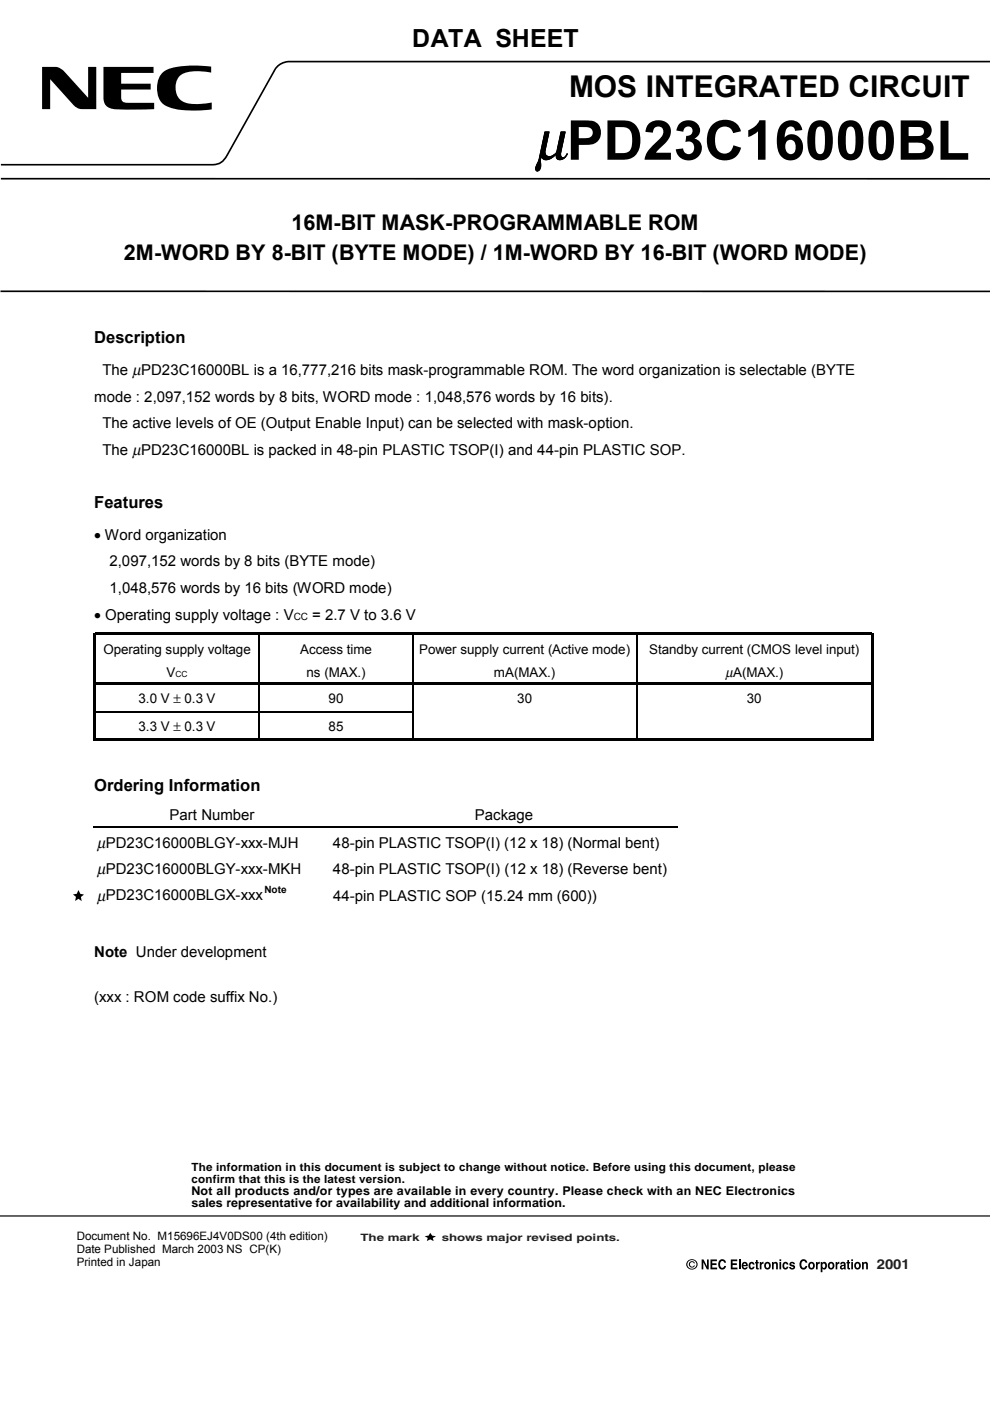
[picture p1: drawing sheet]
<svg xmlns="http://www.w3.org/2000/svg" width="210mm" height="297mm" viewBox="0 0 210 297" stroke-linecap="round" stroke-linejoin="round" font-family="sans-serif">
<defs><g id="words">
<text font-size="11.9" x="113.6" y="33.7">µPD23C16000BL</text>
<text font-size="6.3" x="120.6" y="20.6">MOS INTEGRATED CIRCUIT</text>
<text font-size="5.3" x="87.4" y="9.9">DATA SHEET</text>
<g font-size="4.6">
<text x="61.8" y="48.9">16M-BIT MASK-PROGRAMMABLE ROM</text>
<text x="26.3" y="55.2">2M-WORD BY 8-BIT (BYTE MODE) / 1M-WORD BY 16-BIT (WORD MODE)</text>
</g>
<g font-size="3.5">
<text x="20" y="72.7">Description</text>
<text x="20" y="107.6">Features</text>
<text x="20" y="167.7">Ordering Information</text>
</g>
<g font-size="3.2">
<text x="21.8" y="79.5">The µPD23C16000BL is a 16,777,216 bits mask-programmable ROM. The word organization is selectable (BYTE</text>
<text x="20" y="85.2">mode : 2,097,152 words by 8 bits, WORD mode : 1,048,576 words by 16 bits).</text>
<text x="21.8" y="90.8">The active levels of OE (Output Enable Input) can be selected with mask-option.</text>
<text x="21.8" y="96.4">The µPD23C16000BL is packed in 48-pin PLASTIC TSOP(I) and 44-pin PLASTIC SOP.</text>
<text x="20" y="114.4">• Word organization</text>
<text x="23.2" y="120.1">2,097,152 words by 8 bits (BYTE mode)</text>
<text x="23.2" y="125.7">1,048,576 words by 16 bits (WORD mode)</text>
<text x="20" y="131.4">• Operating supply voltage : V</text>
<text x="66.2" y="131.4">= 2.7 V to 3.6 V</text>
<text x="35.9" y="173.8">Part Number</text>
<text x="100.7" y="173.8">Package</text>
<text x="20.6" y="179.7">µPD23C16000BLGY-xxx-MJH</text>
<text x="70.6" y="179.7">48-pin PLASTIC TSOP(I) (12 x 18) (Normal bent)</text>
<text x="20.6" y="185.3">µPD23C16000BLGY-xxx-MKH</text>
<text x="70.6" y="185.3">48-pin PLASTIC TSOP(I) (12 x 18) (Reverse bent)</text>
<text x="20.6" y="190.9">µPD23C16000BLGX-xxx</text>
<text x="70.6" y="191">44-pin PLASTIC SOP (15.24 mm (600))</text>
<text x="20" y="202.9">Note Under development</text>
<text x="20" y="212.5">(xxx : ROM code suffix No.)</text>
</g>
<text font-size="2.9" x="153.8" y="143.6">µA(MAX.)</text>
<text font-size="2.9" fill="#231f20" x="185.9" y="269.1">2001</text>
<g font-size="2.8">
<text x="21.9" y="138.7">Operating supply voltage</text>
<text x="35.3" y="143.6">V</text>
<text x="63.6" y="138.7">Access time</text>
<text x="65" y="143.6">ns (MAX.)</text>
<text x="88.9" y="138.7">Power supply current (Active mode)</text>
<text x="104.7" y="143.6">mA(MAX.)</text>
<text x="137.6" y="138.7">Standby current (CMOS level input)</text>
<text x="29.4" y="149.1">3.0 V ± 0.3 V</text>
<text x="69.7" y="149.1">90</text>
<text x="109.7" y="149.1">30</text>
<text x="158.4" y="149.1">30</text>
<text x="29.4" y="155">3.3 V ± 0.3 V</text>
<text x="69.7" y="155">85</text>
</g>
<g font-size="2.6">
<text x="40.6" y="253.4">Not all products and/or types are available in every country. Please check with an NEC Electronics</text>
<text x="40.6" y="256">sales representative for availability and additional information.</text>
</g>
<g font-size="2.5">
<text x="16.3" y="262.8">Document No. M15696EJ4V0DS00 (4th edition)</text>
<text x="16.3" y="265.6">Date Published March 2003 NS CP(K)</text>
<text x="16.3" y="268.5">Printed in Japan</text>
</g>
<g font-size="2.4">
<text x="40.6" y="248.3">The information in this document is subject to change without notice. Before using this document, please</text>
<text x="40.6" y="250.8">confirm that this is the latest version.</text>
</g>
<g font-size="2.2" fill="#231f20">
<text x="76.4" y="263">The mark</text>
<text x="93.6" y="263">shows major revised points.</text>
</g>
<g font-size="2.1">
<text x="62.3" y="131.4">CC</text>
<text x="56" y="189.3">Note</text>
</g>
<text font-size="1.8" x="37.2" y="143.6">CC</text>
</g></defs>
<path d="M210 13.1h-148.9a3.5 3.5 0 0 0-3 1.9l-10 17.9a3.2 3.2 0 0 1-3 2h-44.9M.2 37.9h209.8M.1 61.8h209.8" fill="none" stroke="#000" stroke-width=".35"/>
<g fill="#000">
<path d="M8.9 14.2h2.9l1.2 .5 5.7 6v-6.5h1.7v8.9h-3l-1.2-.3-5.6-6v6.3h-1.7zM21.9 14.2h10.7v1.3h-6.9v2.2h6.2v1.3h-6.2v1.6a1.12 1.12 0 0 0 1.5 1.2h5.5v1.3l-7.1 .1a3.9 3.9 0 0 1-3.3-1l-.4-1.4zM34.5 15.4a10.2 10.2 0 0 1 6.2-1.5l4.1 .2v1.3a9.3 9.3 0 0 0-6.4 .5 3.7 3.7 0 0 0 .2 5.5 10.3 10.3 0 0 0 6.3 .3v1.5a21.7 21.7 0 0 1-9.2-.5 4.3 4.3 0 0 1-2.3-5.2 3.8 3.8 0 0 1 1.1-2.1zM19.7 134.2h.5v.5h-.5zM20.2 134.2h34.7v.5h-34.7zM54.9 134.7h.2zM54.9 134.2h32.5v.5h-32.5zM87.4 134.7h.2zM87.4 134.2h47.5v.5h-47.5zM134.9 134.7h.2zM134.9 134.2h49.8v.5h-49.8zM184.7 134.2h.6v.5h-.6z"/>
<path d="M19.7 134.7h.5v9.9h-.5zM19.7 144.6h.5v.5h-.5zM19.7 145.1h.5v5.6h-.5zM19.7 151h.5v6.1h-.5zM20.2 144.6h34.7v.5h-34.7zM20.2 156.6h34.7v.5h-34.7zM54.9 145.1h.2zM54.9 144.6h32.5v.5h-32.5zM54.9 156.6h32.5v.5h-32.5zM87.4 145.1h.2zM87.4 144.6h47.5v.5h-47.5zM87.4 156.6h47.5v.5h-47.5z"/>
<path d="M134.9 145.1h.2zM134.9 144.6h49.8v.5h-49.8zM134.9 150.7h.2v.3h-.2zM134.9 156.6h49.8v.5h-49.8zM184.7 134.7h.6v9.9h-.6zM184.7 144.6h.6v.5h-.6zM184.7 145.1h.6v5.6h-.6zM184.7 150.7h.6v.3h-.6zM184.7 151h.6v6.1h-.6zM15.5 189.6l.8-.1 .3-.8 .4 .8 .8 .2-.6 .5 .1 .9-.7-.5-.7 .4 .2-.9zM90 262.1l.9-.1 .3-.6 .4 .6 .8 .1-.6 .4 .1 .6-.7-.3-.7 .3 .2-.6zM148.8 267h.4l.7 1.5v-1.5h.4v2.1h-.4l-.8-1.5v1.5h-.3z"/>
<path d="M150.6 267h1.4v.4h-1v.4h.9v.4h-.9v.6h1v.3h-1.4zM152.5 267.3a.79 .79 0 0 1 .9-.3 .79 .79 0 0 1 .5 .7h-.4l-.1-.3a.43 .43 0 0 0-.7 .3v.4a.48 .48 0 0 0 .1 .6 .48 .48 0 0 0 .7-.1v-.2h.4a.85 .85 0 0 1-1 .8 .85 .85 0 0 1-.6-1.1zM154.9 267h1.4v.4h-1v.4h.9v.4h-.9v.6h1.1v.3h-1.5zM158.9 267.8a.62 .62 0 0 1 .7-.2 .62 .62 0 0 1 .4 .5h-.4v-.1a.41 .41 0 0 0-.5 .3 .41 .41 0 0 0 .4 .5l.1-.2h.4a.64 .64 0 0 1-.7 .6 .64 .64 0 0 1-.6-.8zM160.3 267.2h.3v.4h.3v.3h-.3v.8l.3 .1v.3l-.6-.1v-1.1h-.2v-.3h.2zM161.1 267.6h.3v.2l.2-.2 .3-.1v.5l-.4 .1v1h-.4zM163.7 267.6h.3v.2l.1-.1a.47 .47 0 0 1 .8 .1v1.3h-.3l-.1-1-.2-.2-.2 .1-.1 1.1h-.3zM166 267.8a.62 .62 0 0 1 .7-.2 .62 .62 0 0 1 .5 .5h-.4l-.1-.1a.41 .41 0 0 0-.4 .3 .41 .41 0 0 0 .4 .5l.1-.2h.4a.64 .64 0 0 1-.8 .6 .64 .64 0 0 1-.5-.8zM167.6 267.6a.62 .62 0 0 1 .9 .4h-.3l-.3-.2-.2 .2 .2 .1a.58 .58 0 0 1 .5 .2 .58 .58 0 0 1 .1 .6l-.5 .3a.57 .57 0 0 1-.7-.6h.4l.3 .3 .2-.2-.1-.1a.57 .57 0 0 1-.7-.8zM169.8 267.3a.79 .79 0 0 1 .8-.3 .79 .79 0 0 1 .6 .7h-.4l-.2-.3a.43 .43 0 0 0-.6 .3l-.1 .4a.48 .48 0 0 0 .2 .6 .48 .48 0 0 0 .6-.1l.1-.2h.4a.85 .85 0 0 1-1 .8 .85 .85 0 0 1-.7-1.1zM173 267.6h.4v.2l.2-.2 .2-.1v.5l-.4 .1v1h-.4zM177.2 267.6h.3v.2l.2-.2 .3-.1v.5l-.4 .1-.1 1h-.3z"/>
<path d="M179.7 267.2h.3v.4h.2v.3h-.2v.8l.2 .1v.3l-.5-.1v-1.1h-.2v-.3h.2zM182.8 267.6h.3v.2l.1-.1a.47 .47 0 0 1 .7 .1l.1 1.3h-.3l-.1-1-.2-.2-.2 .1-.1 1.1h-.3z"/>
<path d="M145.5 268.1a1.16 1.16 0 0 1 2.3 0 1.16 1.16 0 0 1-2.3 0zM145.8 268.1a.95 .95 0 0 0 1.9 0 .95 .95 0 0 0-1.9 0zM146.2 267.6a.67 .67 0 0 1 1.1 .3h-.2a.44 .44 0 0 0-.7-.2 .44 .44 0 0 0 0 .7 .44 .44 0 0 0 .7-.1h.2a.67 .67 0 0 1-1 .3 .67 .67 0 0 1-.1-1z"/>
<path d="M157.6 267.6h.5a.84 .84 0 0 1 .5 .9h-1l.1 .3h.2l.6-.1a.64 .64 0 0 1-.6 .5 .64 .64 0 0 1-.6-.5 1.02 1.02 0 0 1 .3-1.1zM157.8 267.9l-.2 .3h.6l-.2-.3z"/>
<path d="M162.2 267.7a.76 .76 0 0 1 1.2 .6 .76 .76 0 0 1-1.2 .7 1.01 1.01 0 0 1 0-1.3zM162.5 268l-.1 .1a.42 .42 0 0 0 .1 .5 .42 .42 0 0 0 .4 .1l.1-.1a.42 .42 0 0 0 0-.5 .42 .42 0 0 0-.5-.1z"/>
<path d="M165.3 267.6h.3v1.5h-.3zM165.3 267h.3v.4h-.3z"/>
<path d="M171.6 267.7a.76 .76 0 0 1 1.2 .6 .76 .76 0 0 1-1.2 .7 1.01 1.01 0 0 1 0-1.3zM171.8 268l-.1 .1a.42 .42 0 0 0 .1 .5 .42 .42 0 0 0 .5 .1l.1-.1a.42 .42 0 0 0-.1-.5 .42 .42 0 0 0-.5-.1z"/>
<path d="M174 267.6h.4v.2v-.1a.5 .5 0 0 1 .6-.1 .5 .5 0 0 1 .3 .4 .7 .7 0 0 1 0 .8 .7 .7 0 0 1-.9 .2v-.1v.8h-.4zM174.5 268l-.1 .1a.48 .48 0 0 0 .3 .7 .45 .45 0 0 0 .3-.5 .45 .45 0 0 0-.5-.3z"/>
<path d="M175.7 267.7a.76 .76 0 0 1 1.2 .6 .76 .76 0 0 1-1.2 .7 1.01 1.01 0 0 1 0-1.3zM176 268l-.1 .1a.42 .42 0 0 0 .1 .5 .42 .42 0 0 0 .4 .1l.1-.1a.42 .42 0 0 0 0-.5 .42 .42 0 0 0-.5-.1z"/>
<path d="M178.3 267.6l.2-.1a.56 .56 0 0 1 .8 .5l.1 1.1h-.4l-.1-.2a.48 .48 0 0 1-.8 .1 .48 .48 0 0 1 .4-.8l.4-.2-.2-.1-.2 .2h-.4zM178.5 268.5v.3h.3l.1-.4z"/>
<path d="M180.5 267.6h.3v1.5h-.3zM180.5 267h.3v.4h-.3z"/>
<path d="M181.3 267.7a.76 .76 0 0 1 1.2 .6 .76 .76 0 0 1-1.2 .7 1.01 1.01 0 0 1 0-1.3zM181.6 268l-.1 .1a.42 .42 0 0 0 .1 .5 .42 .42 0 0 0 .4 .1l.1-.1a.42 .42 0 0 0 0-.5 .42 .42 0 0 0-.5-.1z"/>
</g>
<path d="M55 134.7v9.9M87.5 134.7v9.9M135 134.7v9.9M19.7 150.9h67.9M55 145.1v5.6M55 151v5.6M87.5 145.1v5.6M87.5 151v5.6M135 145.1v5.6M135 151v5.6M19.9 175.3h123.8M0 257.8h209.9" fill="none" stroke="#000" stroke-width=".25"/>
<path d="M156.8 267v2.1" fill="none" stroke="#000" stroke-width=".36"/>
<use href="#words"/>
</svg>
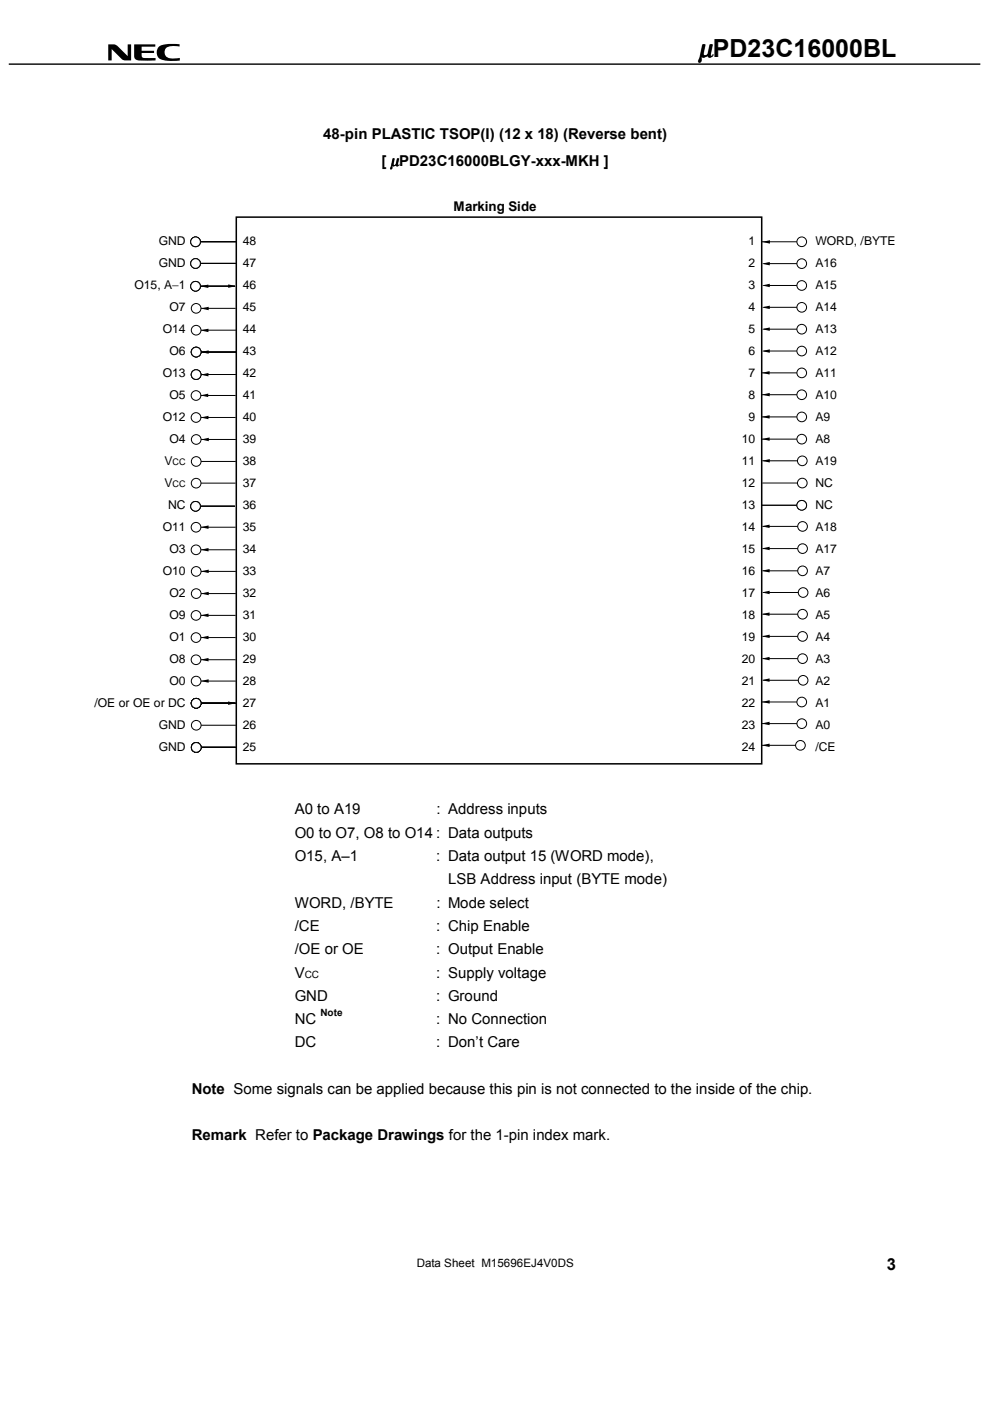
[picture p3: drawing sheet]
<svg xmlns="http://www.w3.org/2000/svg" width="210mm" height="297mm" viewBox="0 0 210 297" stroke-linecap="round" stroke-linejoin="round" font-family="sans-serif">
<defs><g id="words">
<text font-size="5.4" x="148.2" y="12">µPD23C16000BL</text>
<text font-size="3.5" x="188" y="269.2">3</text>
<g font-size="3.2">
<text x="68.5" y="29.5">48-pin PLASTIC TSOP(I) (12 x 18) (Reverse bent)</text>
<text x="80.9" y="35.1">[ µPD23C16000BLGY-xxx-MKH ]</text>
<text x="62.5" y="172.7">A0 to A19</text>
<text x="92.5" y="172.7">: Address inputs</text>
<text x="62.5" y="177.6">O0 to O7, O8 to O14 : Data outputs</text>
<text x="62.5" y="182.6">O15, A–1</text>
<text x="92.5" y="182.6">: Data output 15 (WORD mode),</text>
<text x="95" y="187.5">LSB Address input (BYTE mode)</text>
<text x="62.5" y="192.4">WORD, /BYTE</text>
<text x="62.5" y="197.4">/CE</text>
<text x="92.5" y="197.4">: Chip Enable</text>
<text x="92.5" y="192.4">: Mode select</text>
<text x="62.5" y="202.3">/OE or OE</text>
<text x="92.5" y="202.3">: Output Enable</text>
<text x="62.5" y="207.3">V</text>
<text x="92.5" y="207.3">: Supply voltage</text>
<text x="62.5" y="212.2">GND</text>
<text x="92.5" y="212.2">: Ground</text>
<text x="62.5" y="217">NC</text>
<text x="92.5" y="217">: No Connection</text>
<text x="62.5" y="222.1">DC</text>
<text x="92.5" y="222.1">: Don’t Care</text>
<text x="40.6" y="231.9">Note Some signals can be applied because this pin is not connected to the inside of the chip.</text>
<text x="40.6" y="241.8">Remark Refer to Package Drawings for the 1-pin index mark.</text>
</g>
<text font-size="2.8" x="96.2" y="44.7">Marking Side</text>
<g font-size="2.6">
<text x="33.6" y="51.9">GND</text>
<text x="51.5" y="51.9">48</text>
<text x="158.7" y="51.9">1</text>
<text x="172.9" y="51.9">WORD, /BYTE</text>
<text x="33.6" y="56.6">GND</text>
<text x="51.5" y="56.6">47</text>
<text x="158.7" y="56.6">2</text>
<text x="172.9" y="56.6">A16</text>
<text x="28.5" y="61.2">O15, A−1</text>
<text x="35.9" y="65.9">O7</text>
<text x="51.5" y="61.2">46</text>
<text x="51.5" y="65.9">45</text>
<text x="158.7" y="61.2">3</text>
<text x="158.7" y="65.9">4</text>
<text x="172.9" y="61.2">A15</text>
<text x="172.9" y="65.9">A14</text>
<text x="34.5" y="70.6">O14</text>
<text x="51.5" y="70.6">44</text>
<text x="158.7" y="70.6">5</text>
<text x="172.9" y="70.6">A13</text>
<text x="35.9" y="75.2">O6</text>
<text x="51.5" y="75.2">43</text>
<text x="158.7" y="75.2">6</text>
<text x="172.9" y="75.2">A12</text>
<text x="34.5" y="79.9">O13</text>
<text x="51.5" y="79.9">42</text>
<text x="158.7" y="79.9">7</text>
<text x="172.9" y="79.9">A11</text>
<text x="34.5" y="89.2">O12</text>
<text x="35.9" y="84.5">O5</text>
<text x="51.5" y="84.5">41</text>
<text x="51.5" y="89.2">40</text>
<text x="158.7" y="84.5">8</text>
<text x="158.7" y="89.2">9</text>
<text x="172.9" y="84.5">A10</text>
<text x="172.9" y="89.2">A9</text>
<text x="35.9" y="93.9">O4</text>
<text x="51.5" y="93.9">39</text>
<text x="157.3" y="93.9">10</text>
<text x="172.9" y="93.9">A8</text>
<text x="34.9" y="98.5">V</text>
<text x="51.5" y="98.5">38</text>
<text x="157.3" y="98.5">11</text>
<text x="172.9" y="98.5">A19</text>
<text x="34.9" y="103.2">V</text>
<text x="35.7" y="107.9">NC</text>
<text x="51.5" y="103.2">37</text>
<text x="51.5" y="107.9">36</text>
<text x="157.3" y="103.2">12</text>
<text x="157.3" y="107.9">13</text>
<text x="172.9" y="103.2">NC</text>
<text x="172.9" y="107.9">NC</text>
<text x="34.5" y="112.5">O11</text>
<text x="51.5" y="112.5">35</text>
<text x="157.3" y="112.5">14</text>
<text x="172.9" y="112.5">A18</text>
<text x="35.9" y="117.2">O3</text>
<text x="51.5" y="117.2">34</text>
<text x="157.3" y="117.2">15</text>
<text x="172.9" y="117.2">A17</text>
<text x="34.5" y="121.8">O10</text>
<text x="51.5" y="121.8">33</text>
<text x="157.3" y="121.8">16</text>
<text x="172.9" y="121.8">A7</text>
<text x="35.9" y="126.5">O2</text>
<text x="35.9" y="131.2">O9</text>
<text x="51.5" y="126.5">32</text>
<text x="51.5" y="131.2">31</text>
<text x="157.3" y="126.5">17</text>
<text x="157.3" y="131.2">18</text>
<text x="172.9" y="126.5">A6</text>
<text x="172.9" y="131.2">A5</text>
<text x="35.9" y="135.8">O1</text>
<text x="51.5" y="135.8">30</text>
<text x="157.3" y="135.8">19</text>
<text x="172.9" y="135.8">A4</text>
<text x="35.9" y="140.5">O8</text>
<text x="51.5" y="140.5">29</text>
<text x="157.3" y="140.5">20</text>
<text x="172.9" y="140.5">A3</text>
<text x="20" y="149.8">/OE or OE or DC</text>
<text x="35.9" y="145.2">O0</text>
<text x="51.5" y="145.2">28</text>
<text x="51.5" y="149.8">27</text>
<text x="157.3" y="145.2">21</text>
<text x="157.3" y="149.8">22</text>
<text x="172.9" y="145.2">A2</text>
<text x="172.9" y="149.8">A1</text>
<text x="33.6" y="154.5">GND</text>
<text x="51.5" y="154.5">26</text>
<text x="157.3" y="154.5">23</text>
<text x="172.9" y="154.5">A0</text>
<text x="33.6" y="159.1">GND</text>
<text x="51.5" y="159.1">25</text>
<text x="157.3" y="159.1">24</text>
<text x="172.9" y="159.1">/CE</text>
</g>
<text font-size="2.5" x="88.3" y="268.7">Data Sheet M15696EJ4V0DS</text>
<g font-size="2.1">
<text x="64.6" y="207.3">CC</text>
<text x="67.9" y="215.4">Note</text>
</g>
<g font-size="1.9">
<text x="36.6" y="98.5">CC</text>
<text x="36.6" y="103.2">CC</text>
</g>
</g></defs>
<path d="M1.9 13.6h206" fill="none" stroke="#000" stroke-width=".31"/>
<path d="M23 9.4h1.2l.5 .2 2.4 2.3v-2.5h.7v3.4l-1.7-.1-2.4-2.3v2.4h-.7zM28.4 9.4h4.5v.5h-2.9v.9h2.7v.4h-2.7v.6a.63 .63 0 0 0 .9 .5h2.1v.5h-2.8a1.48 1.48 0 0 1-1.7-.6zM33.6 10a5.9 5.9 0 0 1 4.5-.6v.5l-1.2-.1a1.52 1.52 0 0 0-2 1.3 1.34 1.34 0 0 0 1.6 1.3l1.6-.1v.5a7.1 7.1 0 0 1-4.4-.5l-.4-.5-.1-.7z" fill="#000"/>
<path d="M50.1 46h111.4v115.9h-111.4z" fill="none" stroke="#000" stroke-width=".32"/>
<path d="M161.5 107.1h8.5" fill="none" stroke="#000" stroke-width=".21"/>
<circle cx="170" cy="107.1" r="1.02" fill="#fff" stroke="#000" stroke-width=".21"/>
<path d="M161.5 79.1h8.5" fill="none" stroke="#000" stroke-width=".21"/>
<circle cx="170" cy="79.1" r="1.02" fill="#fff" stroke="#000" stroke-width=".21"/>
<path d="M161.5 51.3h8.5" fill="none" stroke="#000" stroke-width=".21"/>
<circle cx="170" cy="51.3" r="1.02" fill="#fff" stroke="#000" stroke-width=".21"/>
<path d="M161.9 55.9h8.1" fill="none" stroke="#000" stroke-width=".21"/>
<circle cx="170" cy="55.9" r="1.02" fill="#fff" stroke="#000" stroke-width=".21"/>
<path d="M161.6 55.9l1.6-.4v.8z" fill="#000"/>
<path d="M161.9 60.5h8.1" fill="none" stroke="#000" stroke-width=".21"/>
<circle cx="170" cy="60.5" r="1.02" fill="#fff" stroke="#000" stroke-width=".21"/>
<path d="M161.6 60.5l1.6-.3v.7z" fill="#000"/>
<path d="M161.9 65.2h8.1" fill="none" stroke="#000" stroke-width=".21"/>
<circle cx="170" cy="65.2" r="1.02" fill="#fff" stroke="#000" stroke-width=".21"/>
<path d="M161.6 65.2l1.6-.4v.7z" fill="#000"/>
<path d="M161.9 69.8h8.1" fill="none" stroke="#000" stroke-width=".21"/>
<circle cx="170" cy="69.8" r="1.02" fill="#fff" stroke="#000" stroke-width=".21"/>
<path d="M161.6 69.8l1.6-.4v.8z" fill="#000"/>
<path d="M161.9 74.4h8.1" fill="none" stroke="#000" stroke-width=".21"/>
<circle cx="170" cy="74.4" r="1.02" fill="#fff" stroke="#000" stroke-width=".21"/>
<path d="M161.6 74.4l1.6-.3v.7z" fill="#000"/>
<path d="M161.5 83.7h8.5" fill="none" stroke="#000" stroke-width=".21"/>
<circle cx="170" cy="83.7" r="1.02" fill="#fff" stroke="#000" stroke-width=".21"/>
<path d="M161.5 88.4h8.5" fill="none" stroke="#000" stroke-width=".21"/>
<circle cx="170" cy="88.4" r="1.02" fill="#fff" stroke="#000" stroke-width=".21"/>
<path d="M161.5 93.1h8.5" fill="none" stroke="#000" stroke-width=".21"/>
<circle cx="170" cy="93.1" r="1.02" fill="#fff" stroke="#000" stroke-width=".21"/>
<path d="M161.6 97.7h8.5" fill="none" stroke="#000" stroke-width=".21"/>
<circle cx="170.1" cy="97.7" r="1.02" fill="#fff" stroke="#000" stroke-width=".21"/>
<path d="M161.6 102.4h8.5" fill="none" stroke="#000" stroke-width=".21"/>
<circle cx="170.1" cy="102.4" r="1.02" fill="#fff" stroke="#000" stroke-width=".21"/>
<path d="M161.5 107.1h8.5" fill="none" stroke="#000" stroke-width=".21"/>
<circle cx="170" cy="107.1" r="1.02" fill="#fff" stroke="#000" stroke-width=".21"/>
<path d="M161.7 111.6h8.5" fill="none" stroke="#000" stroke-width=".21"/>
<circle cx="170.2" cy="111.6" r="1.02" fill="#fff" stroke="#000" stroke-width=".21"/>
<path d="M161.7 116.3h8.5" fill="none" stroke="#000" stroke-width=".21"/>
<circle cx="170.2" cy="116.3" r="1.02" fill="#fff" stroke="#000" stroke-width=".21"/>
<path d="M161.7 121h8.5" fill="none" stroke="#000" stroke-width=".21"/>
<circle cx="170.2" cy="121" r="1.02" fill="#fff" stroke="#000" stroke-width=".21"/>
<path d="M161.8 125.6h8.5" fill="none" stroke="#000" stroke-width=".21"/>
<circle cx="170.3" cy="125.6" r="1.02" fill="#fff" stroke="#000" stroke-width=".21"/>
<path d="M161.7 130.2h8.5" fill="none" stroke="#000" stroke-width=".21"/>
<circle cx="170.2" cy="130.2" r="1.02" fill="#fff" stroke="#000" stroke-width=".21"/>
<path d="M161.7 134.9h8.5" fill="none" stroke="#000" stroke-width=".21"/>
<circle cx="170.2" cy="134.9" r="1.02" fill="#fff" stroke="#000" stroke-width=".21"/>
<path d="M161.7 139.6h8.5" fill="none" stroke="#000" stroke-width=".21"/>
<circle cx="170.2" cy="139.6" r="1.02" fill="#fff" stroke="#000" stroke-width=".21"/>
<path d="M161.8 144.2h8.5" fill="none" stroke="#000" stroke-width=".21"/>
<circle cx="170.3" cy="144.2" r="1.02" fill="#fff" stroke="#000" stroke-width=".21"/>
<path d="M161.5 148.8h8.5" fill="none" stroke="#000" stroke-width=".21"/>
<circle cx="170" cy="148.8" r="1.02" fill="#fff" stroke="#000" stroke-width=".21"/>
<path d="M161.5 79l1.7-.3v.7zM161.5 93.1l1.7-.4v.8zM161.5 88.4l1.7-.4v.8zM161.6 83.7l1.6-.4v.7zM161.6 97.7l1.6-.4v.8z" fill="#000"/>
<path d="M161.5 153.4h8.5" fill="none" stroke="#000" stroke-width=".21"/>
<circle cx="170" cy="153.4" r="1.02" fill="#fff" stroke="#000" stroke-width=".21"/>
<path d="M161.6 158h8.1" fill="none" stroke="#000" stroke-width=".21"/>
<circle cx="169.7" cy="158" r="1.02" fill="#fff" stroke="#000" stroke-width=".21"/>
<path d="M161.6 51.3l1.6-.4v.8zM161.5 111.6l1.7-.4v.8zM161.5 116.3l1.7-.4v.7zM161.5 130.2l1.7-.3v.7zM161.5 139.6l1.7-.3v.7zM161.5 125.6l1.7-.4v.8zM161.5 121l1.7-.4v.8zM161.5 134.9l1.7-.3v.7zM161.5 153.4l1.7-.4v.7zM161.5 144.2l1.7-.4v.8zM161.5 158l1.7-.3v.7zM161.5 148.8l1.7-.3v.7z" fill="#000"/>
<path d="M41.6 74.6h8.5" fill="none" stroke="#000" stroke-width=".21"/>
<circle cx="41.6" cy="74.6" r="1.02" fill="#fff" stroke="#000" stroke-width=".21"/>
<path d="M41.6 74.6h8.5" fill="none" stroke="#000" stroke-width=".21"/>
<circle cx="41.6" cy="74.6" r="1.02" fill="#fff" stroke="#000" stroke-width=".21"/>
<path d="M41.6 74.6h8.5" fill="none" stroke="#000" stroke-width=".21"/>
<circle cx="41.6" cy="74.6" r="1.02" fill="#fff" stroke="#000" stroke-width=".21"/>
<path d="M41.6 149.1h8.3" fill="none" stroke="#000" stroke-width=".21"/>
<circle cx="41.6" cy="149.1" r="1.02" fill="#fff" stroke="#000" stroke-width=".21"/>
<path d="M41.6 149.1h8.3" fill="none" stroke="#000" stroke-width=".21"/>
<circle cx="41.6" cy="149.1" r="1.02" fill="#fff" stroke="#000" stroke-width=".21"/>
<path d="M41.6 102.4h8.4" fill="none" stroke="#000" stroke-width=".21"/>
<circle cx="41.6" cy="102.4" r="1.02" fill="#fff" stroke="#000" stroke-width=".21"/>
<path d="M41.6 149.1h8.3" fill="none" stroke="#000" stroke-width=".21"/>
<circle cx="41.6" cy="149.1" r="1.02" fill="#fff" stroke="#000" stroke-width=".21"/>
<path d="M41.6 65.4h8.4" fill="none" stroke="#000" stroke-width=".21"/>
<circle cx="41.6" cy="65.4" r="1.02" fill="#fff" stroke="#000" stroke-width=".21"/>
<path d="M41.6 70h8.4" fill="none" stroke="#000" stroke-width=".21"/>
<circle cx="41.6" cy="70" r="1.02" fill="#fff" stroke="#000" stroke-width=".21"/>
<path d="M41.6 74.6h8.5" fill="none" stroke="#000" stroke-width=".21"/>
<circle cx="41.6" cy="74.6" r="1.02" fill="#fff" stroke="#000" stroke-width=".21"/>
<path d="M41.5 107.3h8.3" fill="none" stroke="#000" stroke-width=".21"/>
<circle cx="41.5" cy="107.3" r="1.02" fill="#fff" stroke="#000" stroke-width=".21"/>
<path d="M41.5 107.3h8.3" fill="none" stroke="#000" stroke-width=".21"/>
<circle cx="41.5" cy="107.3" r="1.02" fill="#fff" stroke="#000" stroke-width=".21"/>
<path d="M41.5 107.3h8.3" fill="none" stroke="#000" stroke-width=".21"/>
<circle cx="41.5" cy="107.3" r="1.02" fill="#fff" stroke="#000" stroke-width=".21"/>
<path d="M41.6 79.4h8.3" fill="none" stroke="#000" stroke-width=".21"/>
<circle cx="41.6" cy="79.4" r="1.02" fill="#fff" stroke="#000" stroke-width=".21"/>
<path d="M41.6 79.4h8.3" fill="none" stroke="#000" stroke-width=".21"/>
<circle cx="41.6" cy="79.4" r="1.02" fill="#fff" stroke="#000" stroke-width=".21"/>
<path d="M41.6 79.4h8.3" fill="none" stroke="#000" stroke-width=".21"/>
<circle cx="41.6" cy="79.4" r="1.02" fill="#fff" stroke="#000" stroke-width=".21"/>
<path d="M41.6 149.1h8.3" fill="none" stroke="#000" stroke-width=".21"/>
<circle cx="41.6" cy="149.1" r="1.02" fill="#fff" stroke="#000" stroke-width=".21"/>
<path d="M41.6 149.1h8.3" fill="none" stroke="#000" stroke-width=".21"/>
<circle cx="41.6" cy="149.1" r="1.02" fill="#fff" stroke="#000" stroke-width=".21"/>
<path d="M41.6 149.1h8.3" fill="none" stroke="#000" stroke-width=".21"/>
<circle cx="41.6" cy="149.1" r="1.02" fill="#fff" stroke="#000" stroke-width=".21"/>
<path d="M41.5 51.3h8.6" fill="none" stroke="#000" stroke-width=".21"/>
<circle cx="41.5" cy="51.3" r="1.02" fill="#fff" stroke="#000" stroke-width=".21"/>
<path d="M41.5 51.3h8.6" fill="none" stroke="#000" stroke-width=".21"/>
<circle cx="41.5" cy="51.3" r="1.02" fill="#fff" stroke="#000" stroke-width=".21"/>
<path d="M41.5 51.3h8.6" fill="none" stroke="#000" stroke-width=".21"/>
<circle cx="41.5" cy="51.3" r="1.02" fill="#fff" stroke="#000" stroke-width=".21"/>
<path d="M41.5 55.8h8.5" fill="none" stroke="#000" stroke-width=".21"/>
<circle cx="41.5" cy="55.9" r="1.02" fill="#fff" stroke="#000" stroke-width=".21"/>
<path d="M41.5 55.8h8.5" fill="none" stroke="#000" stroke-width=".21"/>
<circle cx="41.5" cy="55.9" r="1.02" fill="#fff" stroke="#000" stroke-width=".21"/>
<path d="M41.5 55.8h8.5" fill="none" stroke="#000" stroke-width=".21"/>
<circle cx="41.5" cy="55.9" r="1.02" fill="#fff" stroke="#000" stroke-width=".21"/>
<path d="M41.5 60.7h8.3" fill="none" stroke="#000" stroke-width=".21"/>
<circle cx="41.5" cy="60.7" r="1.02" fill="#fff" stroke="#000" stroke-width=".21"/>
<path d="M41.5 60.7h8.3" fill="none" stroke="#000" stroke-width=".21"/>
<circle cx="41.5" cy="60.7" r="1.02" fill="#fff" stroke="#000" stroke-width=".21"/>
<path d="M41.5 60.7h8.3" fill="none" stroke="#000" stroke-width=".21"/>
<circle cx="41.5" cy="60.7" r="1.02" fill="#fff" stroke="#000" stroke-width=".21"/>
<path d="M41.6 144.4h8.4" fill="none" stroke="#000" stroke-width=".21"/>
<circle cx="41.6" cy="144.4" r="1.02" fill="#fff" stroke="#000" stroke-width=".21"/>
<path d="M42.6 144.4l1.6-.4v.8z" fill="#000"/>
<path d="M41.6 139.9h8.4" fill="none" stroke="#000" stroke-width=".21"/>
<circle cx="41.6" cy="139.9" r="1.02" fill="#fff" stroke="#000" stroke-width=".21"/>
<path d="M42.6 139.9l1.6-.4v.7z" fill="#000"/>
<path d="M41.6 88.5h8.4" fill="none" stroke="#000" stroke-width=".21"/>
<circle cx="41.6" cy="88.5" r="1.02" fill="#fff" stroke="#000" stroke-width=".21"/>
<path d="M41.6 93.2h8.4" fill="none" stroke="#000" stroke-width=".21"/>
<circle cx="41.6" cy="93.2" r="1.02" fill="#fff" stroke="#000" stroke-width=".21"/>
<path d="M41.6 97.8h8.4" fill="none" stroke="#000" stroke-width=".21"/>
<circle cx="41.6" cy="97.8" r="1.02" fill="#fff" stroke="#000" stroke-width=".21"/>
<path d="M41.6 83.9h8.4" fill="none" stroke="#000" stroke-width=".21"/>
<circle cx="41.6" cy="83.9" r="1.02" fill="#fff" stroke="#000" stroke-width=".21"/>
<path d="M41.6 111.8h8.4" fill="none" stroke="#000" stroke-width=".21"/>
<circle cx="41.6" cy="111.8" r="1.02" fill="#fff" stroke="#000" stroke-width=".21"/>
<path d="M42.6 111.8l1.6-.4v.7z" fill="#000"/>
<path d="M41.6 116.6h8.4" fill="none" stroke="#000" stroke-width=".21"/>
<circle cx="41.6" cy="116.6" r="1.02" fill="#fff" stroke="#000" stroke-width=".21"/>
<path d="M42.6 116.6l1.6-.4v.7z" fill="#000"/>
<path d="M41.6 121.1h8.4" fill="none" stroke="#000" stroke-width=".21"/>
<circle cx="41.6" cy="121.2" r="1.02" fill="#fff" stroke="#000" stroke-width=".21"/>
<path d="M42.6 121.1l1.7-.3v.7z" fill="#000"/>
<path d="M41.6 125.9h8.4" fill="none" stroke="#000" stroke-width=".21"/>
<circle cx="41.6" cy="125.9" r="1.02" fill="#fff" stroke="#000" stroke-width=".21"/>
<path d="M42.6 125.8l1.7-.3v.7z" fill="#000"/>
<path d="M41.6 130.5h8.4" fill="none" stroke="#000" stroke-width=".21"/>
<circle cx="41.6" cy="130.5" r="1.02" fill="#fff" stroke="#000" stroke-width=".21"/>
<path d="M42.6 130.5l1.6-.4v.7z" fill="#000"/>
<path d="M41.6 135.2h8.4" fill="none" stroke="#000" stroke-width=".21"/>
<circle cx="41.6" cy="135.2" r="1.02" fill="#fff" stroke="#000" stroke-width=".21"/>
<path d="M48.4 60.3l1.6 .4-1.6 .3zM42.6 135.2l1.6-.4v.7zM48.4 148.7l1.6 .4-1.6 .4z" fill="#000"/>
<path d="M41.6 158.4h8.4" fill="none" stroke="#000" stroke-width=".21"/>
<circle cx="41.6" cy="158.5" r="1.02" fill="#fff" stroke="#000" stroke-width=".21"/>
<path d="M41.6 158.4h8.4" fill="none" stroke="#000" stroke-width=".21"/>
<circle cx="41.6" cy="158.5" r="1.02" fill="#fff" stroke="#000" stroke-width=".21"/>
<path d="M41.6 158.4h8.4" fill="none" stroke="#000" stroke-width=".21"/>
<circle cx="41.6" cy="158.5" r="1.02" fill="#fff" stroke="#000" stroke-width=".21"/>
<path d="M41.6 158.4h8.4" fill="none" stroke="#000" stroke-width=".21"/>
<circle cx="41.6" cy="158.5" r="1.02" fill="#fff" stroke="#000" stroke-width=".21"/>
<path d="M41.6 158.4h8.4" fill="none" stroke="#000" stroke-width=".21"/>
<circle cx="41.6" cy="158.5" r="1.02" fill="#fff" stroke="#000" stroke-width=".21"/>
<path d="M41.6 158.4h8.4" fill="none" stroke="#000" stroke-width=".21"/>
<circle cx="41.6" cy="158.5" r="1.02" fill="#fff" stroke="#000" stroke-width=".21"/>
<path d="M41.6 153.8h8.4" fill="none" stroke="#000" stroke-width=".21"/>
<circle cx="41.6" cy="153.8" r="1.02" fill="#fff" stroke="#000" stroke-width=".21"/>
<path d="M42.5 60.7l1.7-.4v.8zM42.5 70.1l1.7-.4v.7zM42.5 79.4l1.7-.3v.7zM42.6 65.4l1.6-.4v.8zM42.6 74.6l1.6-.3v.7zM42.5 83.8l1.6-.3v.7zM42.5 88.5l1.7-.3v.7zM42.6 93.2l1.7-.4v.7z" fill="#000"/>
<use href="#words"/>
</svg>
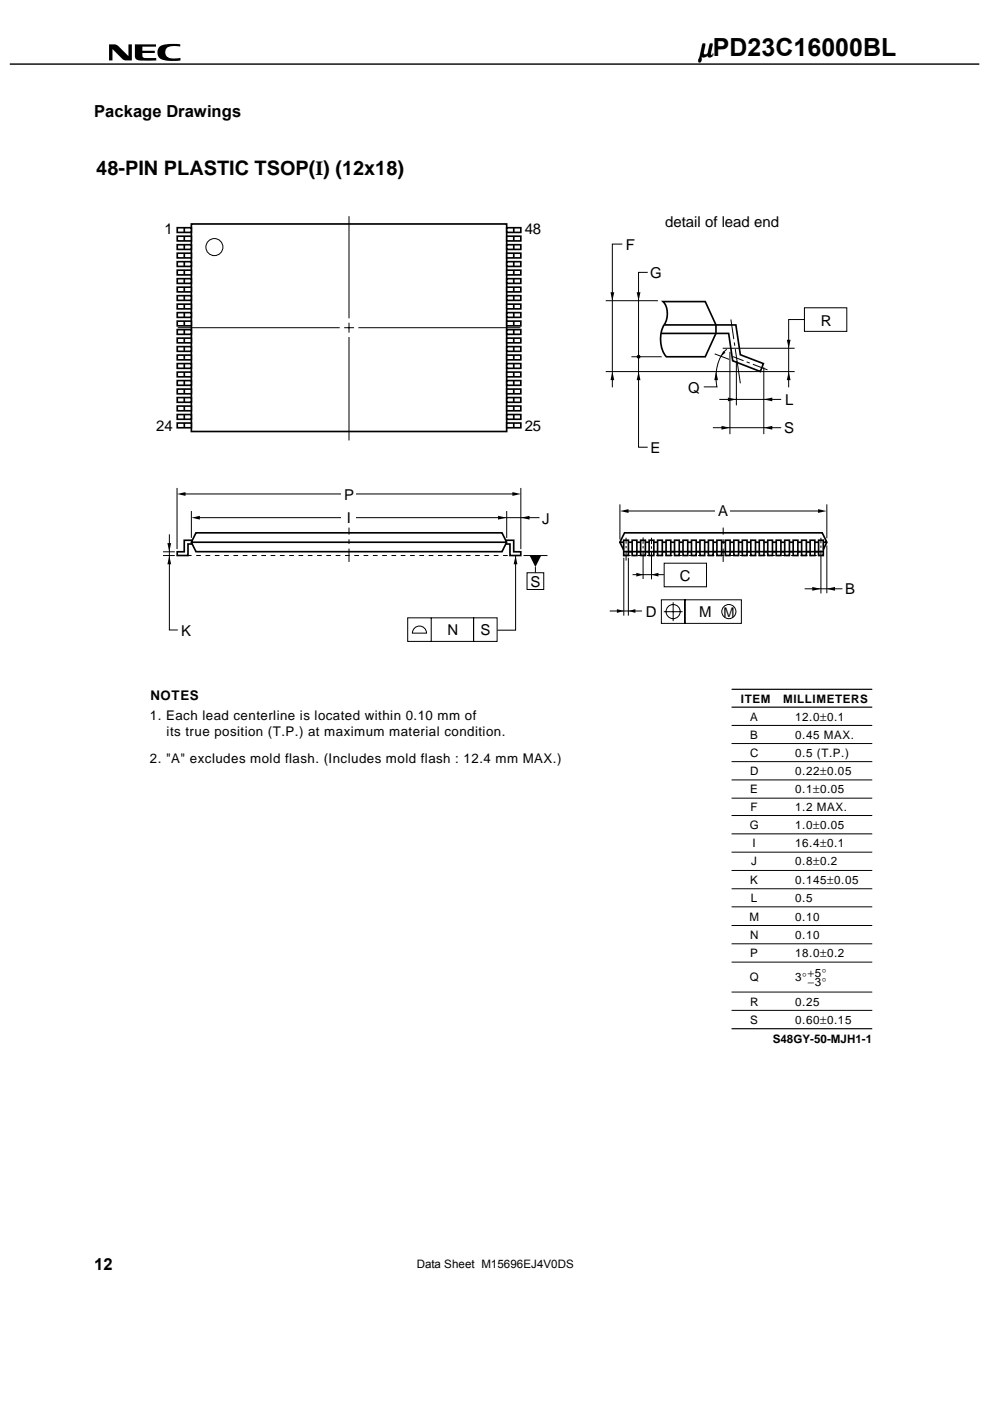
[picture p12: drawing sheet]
<svg xmlns="http://www.w3.org/2000/svg" width="210mm" height="297mm" viewBox="0 0 210 297" stroke-linecap="round" stroke-linejoin="round" font-family="sans-serif">
<defs><g id="words">
<text font-size="5.4" x="148.2" y="11.9">µPD23C16000BL</text>
<text font-size="4.2" x="20.4" y="37.1">48-PIN PLASTIC TSOP(I) (12x18)</text>
<g font-size="3.5">
<text x="20" y="24.9">Package Drawings</text>
<text x="20" y="269.2">12</text>
</g>
<g font-size="3.2">
<text x="34.9" y="49.7">1</text>
<text x="111.2" y="49.7">48</text>
<text x="132.7" y="52.9">F</text>
<text x="141" y="48.2">detail of lead end</text>
<text x="137.9" y="59">G</text>
<text x="174" y="69">R</text>
<text x="145.9" y="83.3">Q</text>
<text x="166.5" y="85.9">L</text>
<text x="33.1" y="91.3">24</text>
<text x="111.2" y="91.3">25</text>
<text x="166.3" y="91.8">S</text>
<text x="137.9" y="96.1">E</text>
<text x="73" y="106">P</text>
<text x="73.5" y="110.9">I</text>
<text x="114.9" y="111.2">J</text>
<text x="152.3" y="109.3">A</text>
<text x="112.5" y="124.4">S</text>
<text x="144.1" y="123.1">C</text>
<text x="179.2" y="125.9">B</text>
<text x="136.9" y="130.9">D</text>
<text x="148.3" y="130.9">M</text>
<text x="38.4" y="134.8">K</text>
<text x="94.9" y="134.7">N</text>
<text x="101.8" y="134.7">S</text>
</g>
<g font-size="2.8">
<text x="153.4" y="130.8">M</text>
<text x="31.9" y="148.3">NOTES</text>
<text x="31.8" y="152.6">1. Each lead centerline is located within 0.10 mm of</text>
<text x="31.8" y="161.7">2. &quot;A&quot; excludes mold flash. (Includes mold flash : 12.4 mm MAX.)</text>
<text x="35.3" y="156.1">its true position (T.P.) at maximum material condition.</text>
</g>
<g font-size="2.5">
<text x="157.1" y="149">ITEM</text>
<text x="166.1" y="149">MILLIMETERS</text>
<text x="159.1" y="152.8">A</text>
<text x="168.6" y="152.8">12.0±0.1</text>
<text x="159" y="160.5">C</text>
<text x="159.1" y="156.6">B</text>
<text x="168.6" y="160.5">0.5 (T.P.)</text>
<text x="168.6" y="156.6">0.45 MAX.</text>
<text x="159" y="164.3">D</text>
<text x="168.6" y="164.3">0.22±0.05</text>
<text x="159.1" y="168.2">E</text>
<text x="159.2" y="172">F</text>
<text x="168.6" y="168.2">0.1±0.05</text>
<text x="168.6" y="172">1.2 MAX.</text>
<text x="159" y="175.7">G</text>
<text x="159.6" y="179.6">I</text>
<text x="168.6" y="179.6">16.4±0.1</text>
<text x="168.6" y="175.7">1.0±0.05</text>
<text x="159.3" y="183.5">J</text>
<text x="168.6" y="183.5">0.8±0.2</text>
<text x="159.1" y="187.4">K</text>
<text x="159.2" y="191.3">L</text>
<text x="168.6" y="187.4">0.145±0.05</text>
<text x="168.6" y="191.3">0.5</text>
<text x="158.9" y="195.2">M</text>
<text x="168.6" y="195.2">0.10</text>
<text x="159" y="199.1">N</text>
<text x="159.1" y="203">P</text>
<text x="168.6" y="199.1">0.10</text>
<text x="168.6" y="203">18.0±0.2</text>
<text x="159" y="208.1">Q</text>
<text x="168.6" y="208.1">3°</text>
<text x="171.3" y="207">+5°</text>
<text x="171.3" y="209.2">−3°</text>
<text x="159" y="213.3">R</text>
<text x="168.6" y="213.3">0.25</text>
<text x="159.1" y="217">S</text>
<text x="163.8" y="221.1">S48GY-50-MJH1-1</text>
<text x="168.6" y="217">0.60±0.15</text>
<text x="88.3" y="268.9">Data Sheet M15696EJ4V0DS</text>
</g>
</g></defs>
<path d="M2.1 13.6h205.5" fill="none" stroke="#000" stroke-width=".31"/>
<path d="M23.1 9.4h1.2l.6 .2 2.3 2.3v-2.5h.8v3.4l-1.8-.1-2.4-2.3v2.4h-.7zM28.6 9.4h4.5v.5h-2.9v.9h2.6v.4h-2.6v.6a.63 .63 0 0 0 .8 .5h2.1v.5h-2.8a1.48 1.48 0 0 1-1.7-.6zM33.7 10a5.9 5.9 0 0 1 4.5-.6v.5l-1.2-.1a1.52 1.52 0 0 0-2 1.3 1.34 1.34 0 0 0 1.7 1.3l1.6-.1v.5a7.1 7.1 0 0 1-4.5-.5l-.3-.5-.1-.7z" fill="#000"/>
<g fill="none" stroke="#000" stroke-width=".21">
<path d="M38.4 104.7h71.1M41.6 109.8h72.8M132.4 108.3h41.6M155.1 153.8h29.8M155.1 157.6h29.8M155.1 161.5h29.8M155.1 165.4h29.8M155.1 172.9h29.8M155.1 169.2h29.8M155.1 176.8h29.8M155.1 188.4h29.8M155.1 180.7h29.8"/>
<path d="M155.1 192.3h29.8M155.1 196.2h29.8M155.1 200.1h29.8M155.1 204h29.8M155.1 210.3h29.8"/>
</g>
<path d="M155.1 149.9h29.8M155.1 146.1h29.8" fill="none" stroke="#000" stroke-width=".25"/>
<path d="M165.7 83.2h3.2v3.1h-3.2z" fill="#fff"/>
<path d="M170.6 65.3h8.9v5h-8.9zM86.4 131h14v5h-14zM88.1 133a1.5 1.5 0 0 1 1.5-.1 1.5 1.5 0 0 1 .8 1.3h-3l.1-.4zM91.4 131v5M100.4 131h5v5h-5zM155.1 184.6h29.8M155.1 214.2h29.8" fill="none" stroke="#000" stroke-width=".21"/>
<path d="M155.1 218.1h29.8" fill="none" stroke="#000" stroke-width=".25"/>
<g fill="#fff">
<path d="M165.7 89.1h3.2v3.2h-3.2z"/>
<path d="M137.3 93.4h3.2v3.1h-3.2z"/>
<path d="M137.4 56.3h3.2v3.2h-3.2z"/>
<path d="M132 50.2h3.1v3.2h-3.1z"/>
</g>
<g fill="none" stroke="#000" stroke-width=".21">
<path d="M140.8 119.4h9v5h-9zM140.2 127.2h5v5h-5zM140.7 129.7h4M142.7 127.7v4M145.2 127.2h12v5h-12z"/>
<circle cx="142.7" cy="129.7" r="1.5"/>
<circle cx="154.5" cy="129.7" r="1.5"/>
</g>
<g fill="#fff">
<path d="M151.7 106.6h3.2v3.2h-3.2z"/>
<path d="M72.3 108.2h3.2v3.2h-3.2z"/>
<path d="M72.4 103.3h3.1v3.1h-3.1z"/>
</g>
<path d="M40.6 47.5h66.8v44h-66.8zM40.7 114.5h-1.6v2.5h-1.5v.8h2.3v-2.5h.8M131.4 115h43.9M132.4 113h41.9l1 2-1 2h-41.9l-1-2z" fill="none" stroke="#000" stroke-width=".35"/>
<path d="M37.6 48.3h3v1h-3z" fill="#fff" stroke="#000" stroke-width=".35"/>
<path d="M39.1 48.3v1" fill="none" stroke="#000" stroke-width=".35"/>
<g fill="#fff" stroke="#000" stroke-width=".35">
<path d="M37.6 50.1h3v1h-3z"/>
<path d="M37.6 51.9h3v1h-3z"/>
<path d="M37.6 53.7h3v1h-3z"/>
<path d="M37.6 55.5h3v1h-3z"/>
<path d="M37.6 57.3h3v1h-3z"/>
<path d="M37.6 59.1h3v1h-3z"/>
<path d="M37.6 60.9h3v1h-3z"/>
<path d="M37.6 62.7h3v1h-3z"/>
<path d="M37.6 64.5h3v1h-3z"/>
<path d="M37.6 66.3h3v1h-3z"/>
<path d="M37.6 68.1h3v1h-3z"/>
<path d="M37.6 69.9h3v1h-3z"/>
<path d="M37.6 71.7h3v1h-3z"/>
<path d="M37.6 73.5h3v1h-3z"/>
<path d="M37.6 75.3h3v1h-3z"/>
<path d="M37.6 77.1h3v1h-3z"/>
<path d="M37.6 78.9h3v1h-3z"/>
<path d="M37.6 80.7h3v1h-3z"/>
<path d="M37.6 82.5h3v1h-3z"/>
<path d="M37.6 84.3h3v1h-3z"/>
<path d="M37.6 86.1h3v1h-3z"/>
<path d="M37.6 87.9h3v1h-3z"/>
<path d="M37.6 89.7h3v1h-3z"/>
</g>
<g fill="none" stroke="#000" stroke-width=".35">
<path d="M39.1 50.1v1M39.1 51.9v1M39.1 53.7v1M39.1 55.5v1M39.1 57.3v1M39.1 59.1v1M39.1 60.9v1M39.1 62.7v1M39.1 64.5v1M39.1 66.3v1M39.1 68.1v1M39.1 69.9v1"/>
<path d="M39.1 71.7v1M39.1 73.5v1M39.1 75.3v1M39.1 77.1v1M39.1 78.9v1M39.1 80.7v1M39.1 82.5v1M39.1 84.3v1M39.1 86.1v1M39.1 87.9v1M39.1 89.7v1"/>
</g>
<path d="M74 45.8v21.7M37.7 69.5h34.3M73 69.5h2.1M74 68.4v2.1M74 71.5v21.9M76 69.5h34.3" fill="none" stroke="#000" stroke-width=".21"/>
<path d="M107.4 48.3h3v1h-3z" fill="#fff" stroke="#000" stroke-width=".35"/>
<path d="M108.9 48.3v1" fill="none" stroke="#000" stroke-width=".35"/>
<g fill="#fff" stroke="#000" stroke-width=".35">
<path d="M107.4 50.1h3v1h-3z"/>
<path d="M107.4 51.9h3v1h-3z"/>
<path d="M107.4 53.7h3v1h-3z"/>
<path d="M107.4 55.5h3v1h-3z"/>
<path d="M107.4 57.3h3v1h-3z"/>
<path d="M107.4 59.1h3v1h-3z"/>
<path d="M107.4 60.9h3v1h-3z"/>
<path d="M107.4 62.7h3v1h-3z"/>
<path d="M107.4 64.5h3v1h-3z"/>
<path d="M107.4 66.3h3v1h-3z"/>
<path d="M107.4 68.1h3v1h-3z"/>
<path d="M107.4 69.9h3v1h-3z"/>
<path d="M107.4 71.7h3v1h-3z"/>
<path d="M107.4 73.5h3v1h-3z"/>
<path d="M107.4 75.3h3v1h-3z"/>
<path d="M107.4 77.1h3v1h-3z"/>
<path d="M107.4 78.9h3v1h-3z"/>
<path d="M107.4 80.7h3v1h-3z"/>
<path d="M107.4 82.5h3v1h-3z"/>
<path d="M107.4 84.3h3v1h-3z"/>
<path d="M107.4 86.1h3v1h-3z"/>
<path d="M107.4 87.9h3v1h-3z"/>
<path d="M107.4 89.7h3v1h-3z"/>
</g>
<g fill="none" stroke="#000" stroke-width=".35">
<path d="M108.9 50.1v1M108.9 51.9v1M108.9 53.7v1M108.9 55.5v1M108.9 57.3v1M108.9 59.1v1M108.9 60.9v1M108.9 62.7v1M108.9 64.5v1M108.9 66.3v1M108.9 68.1v1M108.9 69.9v1"/>
<path d="M108.9 71.7v1M108.9 73.5v1M108.9 75.3v1M108.9 77.1v1M108.9 78.9v1M108.9 80.7v1M108.9 82.5v1M108.9 84.3v1M108.9 86.1v1M108.9 87.9v1M108.9 89.7v1M40.6 115h66.8"/>
<path d="M41.6 113h64.8l1 2-1 2h-64.8l-1-2zM107.3 114.5h1.6v2.5h1.5v.8h-2.3v-2.5h-.8"/>
</g>
<path d="M39.6 117.8h69.5" fill="none" stroke="#000" stroke-width=".21" stroke-dasharray="1 1" stroke-linecap="butt"/>
<path d="M34.6 117h2.5M34.6 117.8h2.5M37.5 103.5v12.9M40.6 108.3v5.7M107.4 108.3v5.7M110.4 103.5v12.9M111 117.8h5.1" fill="none" stroke="#000" stroke-width=".21"/>
<path d="M35.5 115.2h.8l-.4 1.8zM35.9 117.8l.4 1.8h-.8zM37.5 104.7l1.8-.4v.8zM40.6 109.8l1.8-.4v.8zM105.6 109.4l1.8 .4-1.8 .4zM108.6 104.3l1.8 .4-1.8 .4zM110.5 109.8l1.8-.4v.8z" fill="#000"/>
<g fill="#fff" stroke="#000" stroke-width=".35">
<path d="M173.6 114.5h1v3.3h-1z"/>
<path d="M171.8 114.5h1v3.3h-1z"/>
<path d="M170 114.5h1v3.3h-1z"/>
<path d="M168.2 114.5h1v3.3h-1z"/>
<path d="M166.4 114.5h1v3.3h-1z"/>
<path d="M164.6 114.5h1v3.3h-1z"/>
<path d="M162.8 114.5h1v3.3h-1z"/>
<path d="M161 114.5h1v3.3h-1z"/>
<path d="M159.2 114.5h1v3.3h-1z"/>
<path d="M157.4 114.5h1v3.3h-1z"/>
<path d="M155.6 114.5h1v3.3h-1z"/>
<path d="M153.8 114.5h1v3.3h-1z"/>
<path d="M152 114.5h1v3.3h-1z"/>
<path d="M150.2 114.5h1v3.3h-1z"/>
<path d="M148.4 114.5h1v3.3h-1z"/>
<path d="M146.6 114.5h1v3.3h-1z"/>
<path d="M144.8 114.5h1v3.3h-1z"/>
<path d="M143 114.5h1v3.3h-1z"/>
<path d="M141.2 114.5h1v3.3h-1z"/>
<path d="M139.4 114.5h1v3.3h-1z"/>
<path d="M137.6 114.5h1v3.3h-1z"/>
<path d="M135.8 114.5h1v3.3h-1z"/>
<path d="M134 114.5h1v3.3h-1z"/>
<path d="M132.2 114.5h1v3.3h-1z"/>
</g>
<path d="M140.6 63.9h8.9l2.3 5v1.8l-2.3 4.9h-8.2a6.4 6.4 0 0 1-.1-7.3 4.3 4.3 0 0 0-.6-4.4zM140.8 68.9h15.2l1 6.3 4.9 1.9-.7 1.7-5.9-2.3-.8-5.8h-14.4M132.2 117h42.4" fill="none" stroke="#000" stroke-width=".35"/>
<path d="M136.4 122.8v-8.9M138.1 122.8v-8.8" fill="none" stroke="#000" stroke-width=".21" stroke-dasharray="6 .5 .5 .5 2.5" stroke-linecap="butt"/>
<g fill="none" stroke="#000" stroke-width=".21">
<path d="M131.9 51.8h-2.1v30.3M137.3 57.7h-1.9v37.1h1.9M128.4 78.8h40.1M128.4 63.8h11.1M133.9 75.6h6.4M151.5 75l3.1 1.2M153.2 73.8h15.3M154.1 74.1a8 8 0 0 0-2.2 7.1l.1 .8h-2.8M154.8 74.6v17.5M156.1 76.5v9.4M161.9 77.9v14.2M170.5 67.7h-3.3v14.4"/>
<path d="M151.1 90.7h14.5M152.5 84.7h13.1M35.9 113.3v20.3h1.8M109.3 117.8v15.8h-3.9M131.4 106.9v7.5M132.3 118.3v12.2M133.2 118.3v12.2M175.3 106.9v7.2M175.3 115.7v10.1M111.7 121.4h3.6v3.6h-3.6zM113.5 120.2v1.2M129.3 129.5h6.8"/>
<path d="M134.1 121.8h6.7M170.6 124.8h8"/>
</g>
<path d="M174.1 125.8v-11.8" fill="none" stroke="#000" stroke-width=".21" stroke-dasharray="9.2 .5 .5 .5 2.5" stroke-linecap="butt"/>
<g fill="#000">
<path d="M129.4 62h.8l-.4 1.8zM129.8 78.8l.4 1.8h-.8zM135 62h.8l-.4 1.8zM135.4 78.8l.4 1.8h-.8zM151.8 78.8l.4 1.8h-.8zM153.3 74.4l.5 .4-.9 .7zM166.8 72h.8l-.4 1.8zM167.2 78.8l.4 1.8h-.8zM153 90.3l1.8 .4-1.8 .4zM154.3 84.3l1.8 .4-1.8 .4zM161.9 84.7l1.8-.4v.8zM161.9 90.7l1.8-.4v.8z"/>
<path d="M109.3 117.8l.4 1.8h-.8zM131.5 108.4l1.8-.4v.8zM173.5 108l1.7 .4-1.7 .4zM112.3 117.8h2.4l-1.2 2.4zM130.8 129.1l1.5 .4-1.5 .4zM133.3 129.5l1.4-.4v.8zM134.9 121.4l1.5 .4-1.5 .4zM138.1 121.8l1.5-.4v.8zM172.2 124.4l1.8 .4-1.8 .4zM175.2 124.8l1.8-.4v.8z"/>
<circle cx="135.4" cy="75.6" r=".4"/>
</g>
<path d="M132.7 118.9v-4.9" fill="none" stroke="#000" stroke-width=".21" stroke-dasharray="2.1 .5 .5 .5 2.5" stroke-linecap="butt"/>
<path d="M132.2 117.8h42.4" fill="none" stroke="#000" stroke-width=".21" stroke-dasharray=".5" stroke-linecap="butt"/>
<path d="M74 119.1v-7.2M153.3 119.1v-7.2" fill="none" stroke="#000" stroke-width=".21" stroke-dasharray="2.8 1 1 1 2.8" stroke-linecap="butt"/>
<path d="M155.3 75.6l7.4 2.8" fill="none" stroke="#000" stroke-width=".21" stroke-dasharray="2.5 .7 .7 .7 5.3" stroke-linecap="butt"/>
<path d="M155 67.7l2 13.6" fill="none" stroke="#000" stroke-width=".21" stroke-dasharray="4.2 .7 .7 .7 10.6" stroke-linecap="butt"/>
<circle cx="45.5" cy="52.4" r="1.81" fill="#fff" stroke="#000" stroke-width=".21"/>
<use href="#words"/>
</svg>
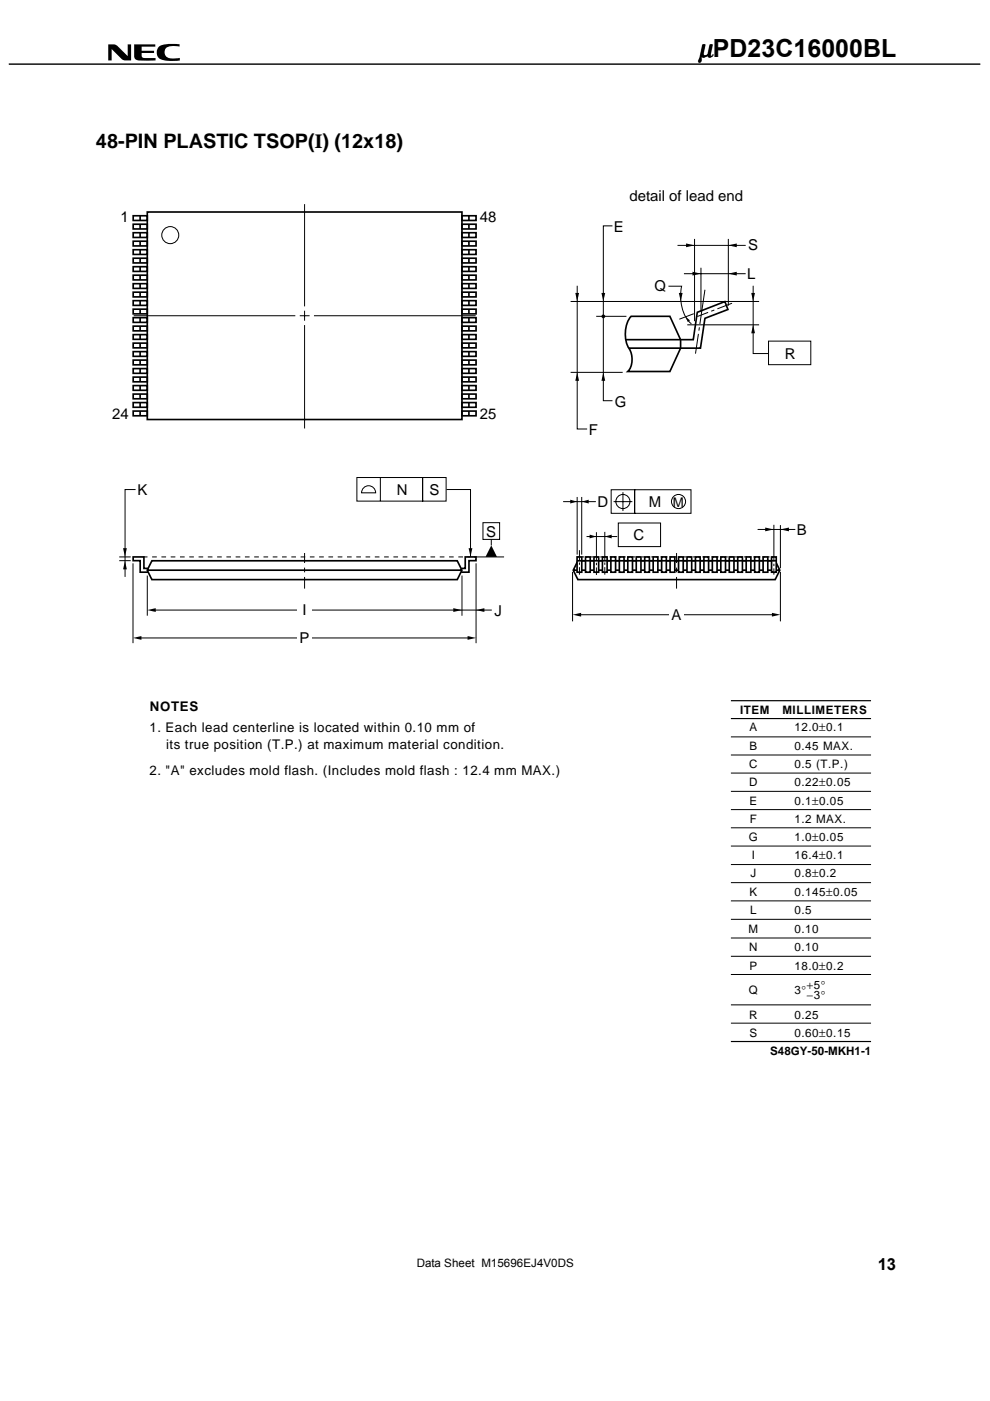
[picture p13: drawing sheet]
<svg xmlns="http://www.w3.org/2000/svg" width="210mm" height="297mm" viewBox="0 0 210 297" stroke-linecap="round" stroke-linejoin="round" font-family="sans-serif">
<defs><g id="words">
<text font-size="5.4" x="148.2" y="12">µPD23C16000BL</text>
<text font-size="4.2" x="20.4" y="31.4">48-PIN PLASTIC TSOP(I) (12x18)</text>
<text font-size="3.5" x="186.1" y="269.2">13</text>
<g font-size="3.2">
<text x="25.5" y="47.1">1</text>
<text x="101.7" y="47.1">48</text>
<text x="133.5" y="42.6">detail of lead end</text>
<text x="130.1" y="49.2">E</text>
<text x="158.7" y="53.1">S</text>
<text x="158.4" y="59.2">L</text>
<text x="138.8" y="61.7">Q</text>
<text x="166.4" y="76">R</text>
<text x="23.8" y="88.8">24</text>
<text x="101.7" y="88.8">25</text>
<text x="130.4" y="86.2">G</text>
<text x="124.8" y="92.2">F</text>
<text x="29.2" y="105">K</text>
<text x="84.1" y="105">N</text>
<text x="91.1" y="105">S</text>
<text x="126.7" y="107.5">D</text>
<text x="137.6" y="107.5">M</text>
<text x="103.1" y="113.8">S</text>
<text x="169" y="113.4">B</text>
<text x="134.3" y="114.4">C</text>
<text x="64.1" y="130.4">I</text>
<text x="104.8" y="130.6">J</text>
<text x="142.4" y="131.5">A</text>
<text x="63.5" y="136.3">P</text>
</g>
<g font-size="2.8">
<text x="142.7" y="107.5">M</text>
<text x="31.7" y="155.3">1. Each lead centerline is located within 0.10 mm of</text>
<text x="31.8" y="150.7">NOTES</text>
<text x="35.2" y="158.8">its true position (T.P.) at maximum material condition.</text>
<text x="31.7" y="164.4">2. &quot;A&quot; excludes mold flash. (Includes mold flash : 12.4 mm MAX.)</text>
</g>
<g font-size="2.5">
<text x="156.9" y="151.4">ITEM</text>
<text x="158.9" y="155.1">A</text>
<text x="165.9" y="151.4">MILLIMETERS</text>
<text x="168.4" y="155.1">12.0±0.1</text>
<text x="158.9" y="159">B</text>
<text x="168.4" y="159">0.45 MAX.</text>
<text x="158.9" y="162.9">C</text>
<text x="158.9" y="166.7">D</text>
<text x="168.4" y="162.9">0.5 (T.P.)</text>
<text x="168.4" y="166.7">0.22±0.05</text>
<text x="158.9" y="170.6">E</text>
<text x="168.4" y="170.6">0.1±0.05</text>
<text x="158.8" y="178.3">G</text>
<text x="159" y="174.5">F</text>
<text x="168.4" y="174.5">1.2 MAX.</text>
<text x="168.4" y="178.3">1.0±0.05</text>
<text x="159.4" y="182.2">I</text>
<text x="168.4" y="182.2">16.4±0.1</text>
<text x="158.9" y="190">K</text>
<text x="159.1" y="186">J</text>
<text x="168.4" y="190">0.145±0.05</text>
<text x="168.4" y="186">0.8±0.2</text>
<text x="158.7" y="197.8">M</text>
<text x="159.1" y="193.9">L</text>
<text x="168.4" y="197.8">0.10</text>
<text x="168.4" y="193.9">0.5</text>
<text x="158.9" y="201.7">N</text>
<text x="168.4" y="201.7">0.10</text>
<text x="158.9" y="205.6">P</text>
<text x="168.4" y="205.6">18.0±0.2</text>
<text x="171.1" y="209.7">+5°</text>
<text x="158.8" y="210.8">Q</text>
<text x="158.9" y="215.9">R</text>
<text x="168.4" y="215.9">0.25</text>
<text x="168.4" y="210.8">3°</text>
<text x="171.1" y="211.9">−3°</text>
<text x="158.9" y="219.8">S</text>
<text x="168.4" y="219.8">0.60±0.15</text>
<text x="163.3" y="223.8">S48GY-50-MKH1-1</text>
<text x="88.3" y="268.7">Data Sheet M15696EJ4V0DS</text>
</g>
</g></defs>
<path d="M1.9 13.6h206" fill="none" stroke="#000" stroke-width=".31"/>
<path d="M23 9.4h1.2l.5 .2 2.4 2.3v-2.5h.7v3.4l-1.7-.1-2.4-2.3v2.4h-.7zM28.4 9.4h4.5v.5h-2.9v.9h2.7v.4h-2.7v.6a.63 .63 0 0 0 .9 .5h2.1v.5h-2.8a1.48 1.48 0 0 1-1.7-.6zM33.6 10a5.9 5.9 0 0 1 4.5-.6v.5l-1.2-.1a1.52 1.52 0 0 0-2 1.3 1.34 1.34 0 0 0 1.6 1.3l1.6-.1v.5a7.1 7.1 0 0 1-4.4-.5l-.4-.5-.1-.7z" fill="#000"/>
<path d="M155 152.4h29.7M155 148.6h29.7" fill="none" stroke="#000" stroke-width=".25"/>
<g fill="none" stroke="#000" stroke-width=".21">
<path d="M155 156.2h29.7M155 160.1h29.7M155 163.9h29.7M155 167.8h29.7M155 175.5h29.7M155 171.7h29.7M155 179.4h29.7M155 191h29.7M155 183.3h29.7M155 194.9h29.7M155 198.9h29.7M155 202.8h29.7"/>
<path d="M155 206.6h29.7M155 213.1h29.7"/>
</g>
<path d="M162.9 72.3h9v5h-9z" fill="#fff" stroke="#000" stroke-width=".21"/>
<g fill="none" stroke="#000" stroke-width=".21">
<path d="M75.7 101.2h13.9v5h-13.9zM77.3 103.3a1.49 1.49 0 0 1 1.5-.1 1.49 1.49 0 0 1 .8 1.3h-2.9v-.5zM80.6 101.2v5M89.6 101.2h5v5h-5zM129.6 103.8h5v5h-5zM130.1 106.4h4M131.1 110.9h9v5h-9zM132.1 104.3v4M134.6 103.8h11.9v5h-11.9zM155 187.1h29.7M155 216.9h29.7"/>
<circle cx="132.1" cy="106.3" r="1.5"/>
<circle cx="143.9" cy="106.3" r="1.5"/>
</g>
<path d="M155 220.8h29.7" fill="none" stroke="#000" stroke-width=".25"/>
<g fill="#fff">
<path d="M104.3 127.9h3.1v3.2h-3.1z"/>
<path d="M129.9 83.5h3.2v3.1h-3.2z"/>
<path d="M158.1 56.5h3.1v3.2h-3.1z"/>
</g>
<path d="M122.5 118.9h41.9l.9 2-.9 2h-41.9l-1-2zM31.4 120.5h-.9v-2.4h-2.3v.8h1.5v2.4h1.7M121.5 120.9h43.8" fill="none" stroke="#000" stroke-width=".35"/>
<path d="M28.2 45.7h3v1h-3z" fill="#fff" stroke="#000" stroke-width=".35"/>
<path d="M29.7 45.7v1" fill="none" stroke="#000" stroke-width=".35"/>
<g fill="#fff" stroke="#000" stroke-width=".35">
<path d="M28.2 47.5h3v1h-3z"/>
<path d="M28.2 49.3h3v1h-3z"/>
<path d="M28.2 51.1h3v1h-3z"/>
<path d="M28.2 52.9h3v1h-3z"/>
<path d="M28.2 54.7h3v1h-3z"/>
<path d="M28.2 56.5h3v1h-3z"/>
<path d="M28.2 58.3h3v1h-3z"/>
<path d="M28.2 60.1h3v1h-3z"/>
<path d="M28.2 61.9h3v1h-3z"/>
<path d="M28.2 63.7h3v1h-3z"/>
<path d="M28.2 65.5h3v1h-3z"/>
<path d="M28.2 67.3h3v1h-3z"/>
<path d="M28.2 69.1h3v1h-3z"/>
<path d="M28.2 70.9h3v1h-3z"/>
<path d="M28.2 72.8h3v.9h-3z"/>
<path d="M28.2 74.6h3v1h-3z"/>
<path d="M28.2 76.4h3v1h-3z"/>
<path d="M28.2 78.2h3v1h-3z"/>
<path d="M28.2 80h3v1h-3z"/>
<path d="M28.2 81.8h3v1h-3z"/>
<path d="M28.2 83.6h3v1h-3z"/>
<path d="M28.2 85.4h3v1h-3z"/>
<path d="M28.2 87.2h3v1h-3z"/>
</g>
<g fill="none" stroke="#000" stroke-width=".35">
<path d="M29.7 47.5v1M29.7 49.3v1M29.7 51.1v1M29.7 52.9v1M29.7 54.7v1M29.7 56.5v1M29.7 58.4v.9M29.7 60.2v.9M29.7 62v.9M29.7 63.8v.9M29.7 65.6v.9M29.7 67.4v.9"/>
<path d="M29.7 69.2v.9M29.7 71v.9M29.7 72.8v.9M29.7 74.6v.9M29.7 76.4v.9M29.7 78.2v.9M29.7 80v.9M29.7 81.8v1M29.7 83.6v1M29.7 85.4v1M29.7 87.2v1"/>
</g>
<path d="M64.6 43.3v21.7M28.3 66.9h34.3M63.6 66.9h2M64.6 65.9v2.1M64.6 68.9v21.9M66.6 66.9h34.2" fill="none" stroke="#000" stroke-width=".21"/>
<path d="M97.9 45.7h3v1h-3z" fill="#fff" stroke="#000" stroke-width=".35"/>
<path d="M99.4 45.7v1" fill="none" stroke="#000" stroke-width=".35"/>
<g fill="#fff" stroke="#000" stroke-width=".35">
<path d="M97.9 47.5h3v1h-3z"/>
<path d="M97.9 49.3h3v1h-3z"/>
<path d="M97.9 51.1h3v1h-3z"/>
<path d="M97.9 52.9h3v1h-3z"/>
<path d="M97.9 54.7h3v1h-3z"/>
<path d="M97.9 56.5h3v1h-3z"/>
<path d="M97.9 58.3h3v1h-3z"/>
<path d="M97.9 60.1h3v1h-3z"/>
<path d="M97.9 61.9h3v1h-3z"/>
<path d="M97.9 63.7h3v1h-3z"/>
<path d="M97.9 65.5h3v1h-3z"/>
<path d="M97.9 67.3h3v1h-3z"/>
<path d="M97.9 69.1h3v1h-3z"/>
<path d="M97.9 70.9h3v1h-3z"/>
<path d="M97.9 72.8h3v.9h-3z"/>
<path d="M97.9 74.6h3v1h-3z"/>
<path d="M97.9 76.4h3v1h-3z"/>
<path d="M97.9 78.2h3v1h-3z"/>
<path d="M97.9 80h3v1h-3z"/>
<path d="M97.9 81.8h3v1h-3z"/>
<path d="M97.9 83.6h3v1h-3z"/>
<path d="M97.9 85.4h3v1h-3z"/>
<path d="M97.9 87.2h3v1h-3z"/>
</g>
<g fill="none" stroke="#000" stroke-width=".35">
<path d="M99.4 47.5v1M99.4 49.3v1M99.4 51.1v1M99.4 52.9v1M99.4 54.7v1M99.4 56.5v1M99.4 58.4v.9M99.4 60.2v.9M99.4 62v.9M99.4 63.8v.9M99.4 65.6v.9M99.4 67.4v.9"/>
<path d="M99.4 69.2v.9M99.4 71v.9M99.4 72.8v.9M99.4 74.6v.9M99.4 76.4v.9M99.4 78.2v.9M99.4 80v.9M99.4 81.8v1M99.4 83.6v1M99.4 85.4v1M99.4 87.2v1M32.2 118.9h64.8l.9 2-.9 2h-64.8l-1-2z"/>
<path d="M31.2 120.9h66.7M97.8 120.5h.8v-2.4h2.3v.8h-1.5v2.4h-1.6"/>
</g>
<path d="M30.3 118.1h69.3" fill="none" stroke="#000" stroke-width=".21" stroke-dasharray="1 1" stroke-linecap="butt"/>
<path d="M25.3 118.1h2.4M25.3 118.9h2.4M28.2 119.4v17M100.9 119.4v17M29.1 135.3h71M31.2 122v8.5M32.3 129.4h72M98 122v8.5" fill="none" stroke="#000" stroke-width=".21"/>
<path d="M26.1 116.2h.8l-.4 1.8zM26.5 118.9l.4 1.8h-.8zM28.2 135.3l1.8-.4v.8zM31.2 129.3l1.8-.4v.8zM96.1 128.9l1.8 .4-1.8 .4zM99.1 134.9l1.8 .4-1.8 .4z" fill="#000"/>
<g fill="#fff" stroke="#000" stroke-width=".35">
<path d="M163.6 118.1h1v3.2h-1z"/>
<path d="M161.8 118.1h1v3.2h-1z"/>
<path d="M160 118.1h1v3.2h-1z"/>
<path d="M158.2 118.1h1v3.2h-1z"/>
<path d="M156.4 118.1h1v3.2h-1z"/>
<path d="M154.6 118.1h1v3.2h-1z"/>
<path d="M152.8 118.1h1v3.2h-1z"/>
<path d="M151 118.1h1v3.2h-1z"/>
<path d="M149.2 118.1h1v3.2h-1z"/>
<path d="M147.5 118.1h.9v3.2h-.9z"/>
<path d="M145.7 118.1h1v3.2h-1z"/>
<path d="M143.9 118.1h1v3.2h-1z"/>
<path d="M142.1 118.1h1v3.2h-1z"/>
<path d="M140.3 118.1h1v3.2h-1z"/>
<path d="M138.5 118.1h1v3.2h-1z"/>
<path d="M136.7 118.1h1v3.2h-1z"/>
<path d="M134.9 118.1h1v3.2h-1z"/>
<path d="M133.1 118.1h1v3.2h-1z"/>
<path d="M131.3 118.1h1v3.2h-1z"/>
<path d="M129.5 118.1h1v3.2h-1z"/>
<path d="M127.7 118.1h1v3.2h-1z"/>
<path d="M125.9 118.1h1v3.2h-1z"/>
<path d="M124.1 118.1h1v3.2h-1z"/>
<path d="M122.4 118.1h.9v3.2h-.9z"/>
</g>
<path d="M31.2 44.9h66.7v44h-66.7zM132.7 72h14.3l.8-5.8 5.9-2.3 .6 1.7-4.8 1.9-1 6.3h-15.2M133.8 67.1h8.2l2.3 4.9v1.8l-2.3 5h-8.9a4.4 4.4 0 0 0-.1-5.5 6.4 6.4 0 0 1 .8-6.2zM122.3 118.9h42.3" fill="none" stroke="#000" stroke-width=".35"/>
<path d="M126.5 112.8v9.1M128.2 112.8v9" fill="none" stroke="#000" stroke-width=".21" stroke-dasharray="6 .5 .5 .5 2.5" stroke-linecap="butt"/>
<g fill="none" stroke="#000" stroke-width=".21">
<path d="M129.9 47.9h-2v37.1h2M143.6 52h14.5M145 58h13.1M147.3 50.7v17.4M148.6 56.8v9.4M154.4 50.7v14.1M121 63.9h40M121 78.9h11M122.4 60.6v30.4h2.1M126.4 67.1h6.4M141.7 60.7h2.8a9.2 9.2 0 0 0 1.5 7.5l.6 .4M145.7 68.9h15.3"/>
<path d="M147.1 66.5l-3.1 1.2M159.7 60.6v14.4h3.3M28.7 103.8h-2.2v18.5M94.7 103.8h5.1v14.2M100.5 118.1h6.4M102.4 110.8h3.5v3.6h-3.5zM104.2 114.4v1.2M119.4 106.4h6.9M122.4 105.4v12.2M123.3 105.4v12.2M124.4 113.8h6.5M160.6 112.3h8"/>
<path d="M165.5 111.3v9.2M121.4 121.2v10.5M122.5 130.3h41.8M165.5 121.3v10.4"/>
</g>
<path d="M164.1 111.3v10.5" fill="none" stroke="#000" stroke-width=".21" stroke-dasharray="7.7 .5 .5 .5 2.5" stroke-linecap="butt"/>
<g fill="#000">
<path d="M145.5 51.6l1.8 .4-1.8 .4zM146.8 57.6l1.8 .4-1.8 .4zM154.4 58l1.8-.4v.8zM154.4 52l1.8-.4v.8zM122.4 78.9l.4 1.8h-.8zM122 62.1h.8l-.4 1.8zM127.9 78.9l.4 1.8h-.8zM127.5 62.1h.8l-.4 1.8zM143.9 62.1h.8l-.4 1.8zM145.4 67.2l.9 .7-.5 .4zM159.7 68.9l.4 1.8h-.8zM159.3 62.1h.8l-.4 1.8z"/>
<path d="M99.4 116.2h.8l-.4 1.8zM104.2 115.6l1.2 2.5h-2.5zM120.9 105.9l1.5 .4-1.5 .4zM123.4 106.3l1.4-.4v.8zM125 113.4l1.5 .4-1.5 .4zM128.2 113.8l1.5-.4v.8zM162.2 111.9l1.8 .4-1.8 .4zM165.5 112.3l1.8-.4v.8zM100.9 129.3l1.8-.4v.8zM121.4 130.3l1.8-.4v.8zM163.7 129.9l1.8 .4-1.8 .4z"/>
<circle cx="127.9" cy="67.1" r=".4"/>
</g>
<path d="M122.9 116.6v5.2" fill="none" stroke="#000" stroke-width=".21" stroke-dasharray="2.1 .5 .5 .5 2.5" stroke-linecap="butt"/>
<path d="M122.4 118.1h42.2" fill="none" stroke="#000" stroke-width=".21" stroke-dasharray=".5" stroke-linecap="butt"/>
<path d="M64.6 124.8v-7.5M143.4 124.8v-7.5" fill="none" stroke="#000" stroke-width=".21" stroke-dasharray="2.5 1 1 1 3.5" stroke-linecap="butt"/>
<path d="M147.8 67.1l7.4-2.8" fill="none" stroke="#000" stroke-width=".21" stroke-dasharray="2.5 .7 .7 .7 5.3" stroke-linecap="butt"/>
<path d="M147.5 75l2-13.6" fill="none" stroke="#000" stroke-width=".21" stroke-dasharray="4.2 .7 .7 .7 10.6" stroke-linecap="butt"/>
<circle cx="36.1" cy="49.9" r="1.8" fill="#fff" stroke="#000" stroke-width=".21"/>
<g fill="#fff">
<path d="M141.9 128.7h3.1v3.2h-3.1z"/>
<path d="M63 127.7h3.2v3.2h-3.2z"/>
<path d="M63 133.6h3.1v3.2h-3.1z"/>
</g>
<use href="#words"/>
</svg>
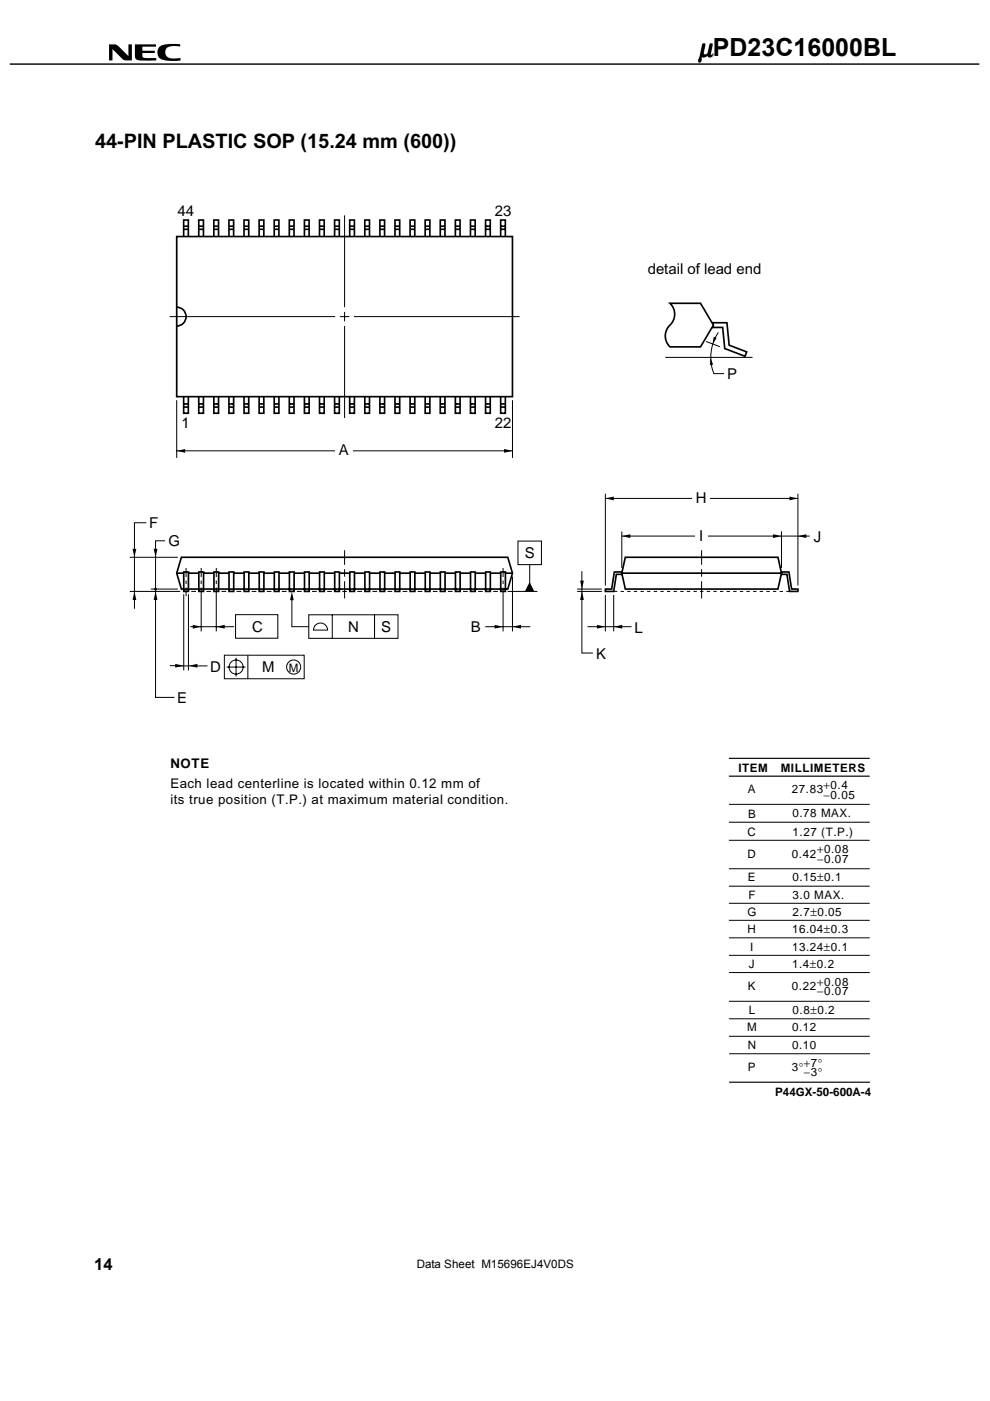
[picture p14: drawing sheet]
<svg xmlns="http://www.w3.org/2000/svg" width="210mm" height="297mm" viewBox="0 0 210 297" stroke-linecap="round" stroke-linejoin="round" font-family="sans-serif">
<defs><g id="words">
<text font-size="5.4" x="148.2" y="11.9">µPD23C16000BL</text>
<text font-size="4.2" x="20.2" y="31.4">44-PIN PLASTIC SOP (15.24 mm (600))</text>
<text font-size="3.5" x="20" y="269.2">14</text>
<g font-size="3.2">
<text x="37.6" y="45.8">44</text>
<text x="104.9" y="45.8">23</text>
<text x="137.3" y="58.1">detail of lead end</text>
<text x="154.2" y="80.4">P</text>
<text x="38.5" y="90.8">1</text>
<text x="104.9" y="90.8">22</text>
<text x="71.8" y="96.4">A</text>
<text x="147.5" y="106.7">H</text>
<text x="31.7" y="112">F</text>
<text x="35.7" y="115.8">G</text>
<text x="111.3" y="118.4">S</text>
<text x="148.2" y="114.6">I</text>
<text x="172.6" y="115">J</text>
<text x="53.4" y="134">C</text>
<text x="73.8" y="134">N</text>
<text x="80.8" y="134">S</text>
<text x="99.9" y="133.9">B</text>
<text x="134.6" y="134.1">L</text>
<text x="44.6" y="142.4">D</text>
<text x="55.6" y="142.4">M</text>
<text x="126.4" y="139.7">K</text>
<text x="37.5" y="149.1">E</text>
</g>
<g font-size="2.8">
<text x="36.1" y="162.8">NOTE</text>
<text x="36.1" y="167.1">Each lead centerline is located within 0.12 mm of</text>
<text x="36.1" y="170.5">its true position (T.P.) at maximum material condition.</text>
</g>
<g font-size="2.5">
<text x="61.2" y="142.4">M</text>
<text x="156.6" y="163.6">ITEM</text>
<text x="165.5" y="163.6">MILLIMETERS</text>
<text x="174.6" y="167.2">+0.4</text>
<text x="158.6" y="168.2">A</text>
<text x="158.6" y="173.3">B</text>
<text x="167.9" y="168.2">27.83</text>
<text x="168" y="173.3">0.78 MAX.</text>
<text x="174.6" y="169.3">−0.05</text>
<text x="158.5" y="177.2">C</text>
<text x="168" y="177.2">1.27 (T.P.)</text>
<text x="158.5" y="181.9">D</text>
<text x="167.9" y="181.9">0.42</text>
<text x="173.3" y="180.9">+0.08</text>
<text x="173.3" y="183">−0.07</text>
<text x="158.6" y="186.9">E</text>
<text x="158.7" y="190.5">F</text>
<text x="168" y="186.9">0.15±0.1</text>
<text x="168" y="190.5">3.0 MAX.</text>
<text x="158.5" y="194.1">G</text>
<text x="158.5" y="197.9">H</text>
<text x="167.9" y="197.9">16.04±0.3</text>
<text x="168" y="194.1">2.7±0.05</text>
<text x="159.1" y="201.6">I</text>
<text x="167.9" y="201.6">13.24±0.1</text>
<text x="158.6" y="210">K</text>
<text x="158.8" y="205.3">J</text>
<text x="167.9" y="210">0.22</text>
<text x="167.9" y="205.2">1.4±0.2</text>
<text x="173.3" y="209">+0.08</text>
<text x="158.7" y="215">L</text>
<text x="168" y="215">0.8±0.2</text>
<text x="173.3" y="211.1">−0.07</text>
<text x="158.4" y="218.7">M</text>
<text x="167.9" y="218.7">0.12</text>
<text x="158.5" y="222.4">N</text>
<text x="158.6" y="227.1">P</text>
<text x="167.9" y="227.1">3°</text>
<text x="167.9" y="222.3">0.10</text>
<text x="170.5" y="226.1">+7°</text>
<text x="164.4" y="232.3">P44GX-50-600A-4</text>
<text x="170.5" y="228.2">−3°</text>
<text x="88.3" y="268.9">Data Sheet M15696EJ4V0DS</text>
</g>
</g></defs>
<path d="M2.1 13.6h205.5" fill="none" stroke="#000" stroke-width=".31"/>
<path d="M23.1 9.4h1.2l.6 .2 2.3 2.3v-2.5h.8v3.4l-1.8-.1-2.4-2.3v2.4h-.7zM28.6 9.4h4.5v.5h-2.9v.9h2.6v.4h-2.6v.6a.63 .63 0 0 0 .8 .5h2.1v.5h-2.8a1.48 1.48 0 0 1-1.7-.6zM33.7 10a5.9 5.9 0 0 1 4.5-.6v.5l-1.2-.1a1.52 1.52 0 0 0-2 1.3 1.34 1.34 0 0 0 1.7 1.3l1.6-.1v.5a7.1 7.1 0 0 1-4.5-.5l-.3-.5-.1-.7z" fill="#000"/>
<path d="M154.5 164.6h29.9M154.5 160.8h29.9M154.6 229.4h29.8" fill="none" stroke="#000" stroke-width=".25"/>
<g fill="none" stroke="#000" stroke-width=".21">
<path d="M154.5 170.5h29.9M154.5 174.3h29.9M154.5 178.2h29.9M154.5 184.2h29.9M154.5 187.9h29.9M154.5 191.5h29.9M154.5 195.1h29.9M154.5 198.8h29.9M154.5 202.5h29.9M154.5 206.2h29.9M154.5 216h29.9M154.5 219.7h29.9"/>
<path d="M154.5 212.3h29.9M154.6 223.4h29.8"/>
</g>
<g fill="#fff">
<path d="M125.7 136.5h3.2v4h-3.2z"/>
<path d="M133.9 131h3.1v4h-3.1z"/>
<path d="M34.9 112.7h3.7v4h-3.7z"/>
<path d="M153.5 77.3h3.8v4h-3.8z"/>
<path d="M43.9 139.3h3.7v4h-3.7z"/>
<path d="M99.1 130.8h3.7v4h-3.7z"/>
<path d="M171.6 111.9h3.7v4h-3.7z"/>
</g>
<g fill="none" stroke="#000" stroke-width=".21">
<path d="M47.6 138.9h16.9v5h-16.9zM50.1 139.4v4M52.6 138.9v5M65.5 130.3h13.9v5h-13.9zM67.1 132.4a1.49 1.49 0 0 1 1.5-.2 1.49 1.49 0 0 1 .9 1.4h-3v-.5zM70.4 130.3v5M79.4 130.3h5v5h-5zM48.1 141.4h3.9"/>
<circle cx="50.1" cy="141.4" r="1.5"/>
<circle cx="62.3" cy="141.4" r="1.5"/>
</g>
<g fill="#fff">
<path d="M31 108.9h3.7v4h-3.7z"/>
<path d="M36.9 146h3.7v4h-3.7z"/>
</g>
<path d="M112.3 117.2v6.7M49.9 130.3h9v5h-9z" fill="none" stroke="#000" stroke-width=".21"/>
<path d="M109.8 114.7h5v5h-5z" fill="#fff" stroke="#000" stroke-width=".21"/>
<g fill="#000">
<path d="M150.7 75.9l.5 1.4-.7 .1zM151.3 71.4l.7 .3-.9 1.2zM37.5 95.6l1.8-.4v.8zM106.9 95.2l1.8 .4-1.8 .4zM28.1 116.4h.8l-.4 1.8zM32.6 116.4h.8l-.4 1.8zM128.4 105.7l1.7-.4v.8zM131.8 113.7l1.8-.4v.8zM163.9 113.3l1.8 .4-1.8 .4zM169.2 113.7l1.8-.4v.8zM167.4 105.3l1.8 .4-1.8 .4zM28.5 125.4l.4 1.8h-.8z"/>
<path d="M33 125.4l.4 1.8h-.8zM40.9 132.5l1.8 .4-1.8 .4zM45.9 132.9l1.8-.4v.8zM61.9 125.5l.4 1.8h-.8zM104.9 132.5l1.8 .4-1.8 .4zM108.7 132.9l1.8-.4v.8zM112.3 123.4l1 2h-2zM123.4 125.4l.4 1.8h-.8zM123 123.1h.8l-.4 1.8zM126.6 132.5l1.8 .4-1.8 .4zM130.1 132.9l1.8-.4v.8zM37.1 140.8l1.8 .3-1.8 .4z"/>
<path d="M40.1 141.1l1.8-.3v.7z"/>
<circle cx="33" cy="124.9" r=".3"/>
</g>
<g fill="none" stroke="#000" stroke-width=".21">
<path d="M73.1 45.7v19.4M36 67.1h35.1M72.1 67.1h2M73.1 66.1v2M73.1 69.1v19.5M75.1 67.1h35.1M141.1 75.8h18.5M149.7 72.4l2.9 1.1M152.3 70.5a9.5 9.5 0 0 0-1 8.7h2.2M37.5 84.9v12.2M37.5 95.6h71.2M108.7 84.9v12.2"/>
<path d="M27.5 118.2h10.2M31 110.8h-2.5v18.3M35 114.7h-2v33.2h4M73.1 116.7v3.1M128.4 105.7h40.8M128.4 104.7v19.4M131.8 113.7h39.9M131.8 112.7v7.7M148.8 116.7v3.1M165.7 112.7v7.7M169.2 104.7v19.4M27.5 125.4h10.7"/>
<path d="M32 124.9h5.7M39 126v16.1M39.5 120.4v1.9M39.5 123.1v.7M39.5 124.6v1.8M40 126v16.1M40.3 132.9h9.3M40.6 125.4h1M42.7 120.4v1.9M42.7 123.1v.7M42.7 124.6v9.3M43.8 125.4h1"/>
<path d="M45.9 120.4v1.9M45.9 123.1v.7M45.9 124.6v9.3M47 125.4h1M50.2 125.4h1M53.4 125.4h1M56.6 125.4h1M59.8 125.4h1M61.9 126.7v6.2h3.6M63 125.4h1M66.2 125.4h1M69.4 125.4h1"/>
<path d="M72.6 125.4h1M73.1 120.7v1.6M73.1 123.2v3.7M75.8 125.4h1M79 125.4h1M82.2 125.4h1M85.4 125.4h1M88.6 125.4h1M91.8 125.4h1M95 125.4h1M98.2 125.4h1M101.4 125.4h1"/>
<path d="M102.9 132.9h9.5M104.6 125.4h1M106.7 120.4v1.9M106.7 123.1v.7M106.7 124.6v9.3M107.6 125.4h6.3M108.7 122.3v11.6M122.4 124.9h5.2M122.4 125.4h5.2M123.4 121.1v17.4h2.3M124.6 132.9h9.3M128.4 126.1v7.8"/>
<path d="M130.1 126.1v7.8M148.8 120.7v1.6M148.8 123.2v3.7M36 141.1h2M37.7 141.2h6.3"/>
</g>
<path d="M167.4 125.4h-37.3" fill="none" stroke="#000" stroke-width=".21" stroke-dasharray=".7" stroke-linecap="butt"/>
<g fill="none" stroke="#000" stroke-width=".35">
<path d="M37.5 50.2h71.2v33.9h-71.2zM38.9 50.1v-3.4h1v3.4M38.9 48.6h1M38.9 48h1M42.1 50.1v-3.4h1v3.4M42.1 48.6h1M42.1 48h1M45.3 50.1v-3.4h1v3.4M45.3 48.6h1M45.3 48h1M48.5 48.6h1M48.5 48h1"/>
<path d="M48.5 50.1v-3.4h1v3.4M51.7 50.1v-3.4h1v3.4M51.7 48.6h1M51.7 48h1M54.9 50.1v-3.4h1v3.4M54.9 48.6h1M54.9 48h1M58.1 50.1v-3.4h1v3.4M58.1 48.6h1M58.1 48h1M61.3 48.6h1M61.3 48h1"/>
<path d="M61.3 50.1v-3.4h1v3.4M64.5 50.1v-3.4h1v3.4M64.5 48.6h1M64.5 48h1M67.7 50.1v-3.4h1v3.4M67.7 48.6h1M67.7 48h1M70.9 50.1v-3.4h1v3.4M70.9 48.6h1M70.9 48h1M74.1 48.6h1M74.1 48h1"/>
<path d="M74.1 50.1v-3.4h1v3.4M77.3 50.1v-3.4h1v3.4M77.3 48.6h1M77.3 48h1M80.5 50.1v-3.4h1v3.4M80.5 48.6h1M80.5 48h1M83.7 50.1v-3.4h1v3.4M83.7 48.6h1M83.7 48h1M86.9 48.6h1M86.9 48h1"/>
<path d="M86.9 50.1v-3.4h1v3.4M90.1 50.1v-3.4h1v3.4M90.1 48.6h1M90.1 48h1M93.3 50.1v-3.4h1v3.4M93.3 48.6h1M93.3 48h1M96.5 50.1v-3.4h1v3.4M96.5 48.6h1M96.5 48h1M99.7 48.6h1M99.7 48h1"/>
<path d="M99.7 50.1v-3.4h1v3.4M102.9 48.6h1M102.9 48h1M102.9 50.1v-3.4h1v3.4M106.1 50.1v-3.4h1v3.4M106.1 48.6h1M106.1 48h1M37.5 65.1a2 2 0 0 1 2 2 2 2 0 0 1-2 2M142.1 64.3h6.4l2.8 4.6-2.8 4.6h-6.4a3.3 3.3 0 0 1 .3-4.9 3.2 3.2 0 0 0-.3-4.3zM151 68.4h3.1l.5 4.8 3.7 1.4-.3 .9-4.3-1.6-.5-4.5h-2.2M38.9 84.1v3.5h1v-3.5M38.9 85.6h1"/>
<path d="M38.9 86.3h1M42.1 84.1v3.5h1v-3.5M42.1 85.6h1M42.1 86.3h1M45.3 84.1v3.5h1v-3.5M45.3 85.6h1M45.3 86.3h1M48.5 85.6h1M48.5 86.3h1M48.5 84.1v3.5h1v-3.5M51.7 84.1v3.5h1v-3.5M51.7 85.6h1"/>
<path d="M51.7 86.3h1M54.9 84.1v3.5h1v-3.5M54.9 85.6h1M54.9 86.3h1M58.1 84.1v3.5h1v-3.5M58.1 85.6h1M58.1 86.3h1M61.3 85.6h1M61.3 86.3h1M61.3 84.1v3.5h1v-3.5M64.5 84.1v3.5h1v-3.5M64.5 85.6h1"/>
<path d="M64.5 86.3h1M67.7 84.1v3.5h1v-3.5M67.7 85.6h1M67.7 86.3h1M70.9 84.1v3.5h1v-3.5M70.9 85.6h1M70.9 86.3h1M74.1 85.6h1M74.1 86.3h1M74.1 84.1v3.5h1v-3.5M77.3 84.1v3.5h1v-3.5M77.3 85.6h1"/>
<path d="M77.3 86.3h1M80.5 84.1v3.5h1v-3.5M80.5 85.6h1M80.5 86.3h1M83.7 84.1v3.5h1v-3.5M83.7 85.6h1M83.7 86.3h1M86.9 85.6h1M86.9 86.3h1M86.9 84.1v3.5h1v-3.5M90.1 84.1v3.5h1v-3.5M90.1 85.6h1"/>
<path d="M90.1 86.3h1M93.3 84.1v3.5h1v-3.5M93.3 85.6h1M93.3 86.3h1M96.5 84.1v3.5h1v-3.5M96.5 85.6h1M96.5 86.3h1M99.7 85.6h1M99.7 86.3h1M99.7 84.1v3.5h1v-3.5M102.9 85.6h1M102.9 86.3h1"/>
<path d="M102.9 84.1v3.5h1v-3.5M106.1 84.1v3.5h1v-3.5M106.1 85.6h1M106.1 86.3h1M38.5 118.2h69.2l1 3.3-1 3.4h-69.2l-1-3.4zM132.6 118.2h32.3l.8 3.3-.8 3.4h-32.3l-.8-3.4zM37.5 121.5h1.5M39 121.3h1v4.1h-1zM40 121.5h2.2M42.2 121.3h1v4.1h-1zM43.2 121.5h2.2M45.4 121.3h1v4.1h-1z"/>
<path d="M46.4 121.5h2.2M48.6 121.3h1v4.1h-1zM49.6 121.5h2.2M51.8 121.3h1v4.1h-1zM52.8 121.5h2.2M55 121.3h1v4.1h-1zM56 121.5h2.2M58.2 121.3h1v4.1h-1zM59.2 121.5h2.2M61.4 121.3h1v4.1h-1zM62.4 121.5h2.2M64.6 121.3h1v4.1h-1z"/>
<path d="M65.6 121.5h2.2M67.8 121.3h1v4.1h-1zM68.8 121.5h2.2M71 121.3h1v4.1h-1zM72 121.5h2.2M74.2 121.3h1v4.1h-1zM75.2 121.5h2.2M77.4 121.3h1v4.1h-1zM78.4 121.5h2.2M80.6 121.3h1v4.1h-1zM81.6 121.5h2.2M83.8 121.3h1v4.1h-1z"/>
<path d="M84.8 121.5h2.2M87 121.3h1v4.1h-1zM88 121.5h2.2M90.2 121.3h1v4.1h-1zM91.2 121.5h2.2M93.4 121.3h1v4.1h-1zM94.4 121.5h2.2M96.6 121.3h1v4.1h-1zM97.6 121.5h2.2M99.8 121.3h1v4.1h-1zM100.8 121.5h2.2M103 121.3h1v4.1h-1z"/>
<path d="M104 121.5h2.2M106.2 121.3h1v4.1h-1zM107.2 121.5h1.5M131.8 121.5h33.9M131.9 121.3h-1.6l-.6 3.6h-1.3v.5h1.7l.6-3.6h1.2M165.6 121.3h1.7l.5 3.6h1.4v.5h-1.8l-.6-3.6h-1.2"/>
</g>
<g fill="#fff">
<path d="M146.8 103.6h3.7v4h-3.7z"/>
<path d="M147.4 111.6h2.7v4h-2.7z"/>
<path d="M71.1 93.3h3.7v4h-3.7z"/>
</g>
<use href="#words"/>
</svg>
